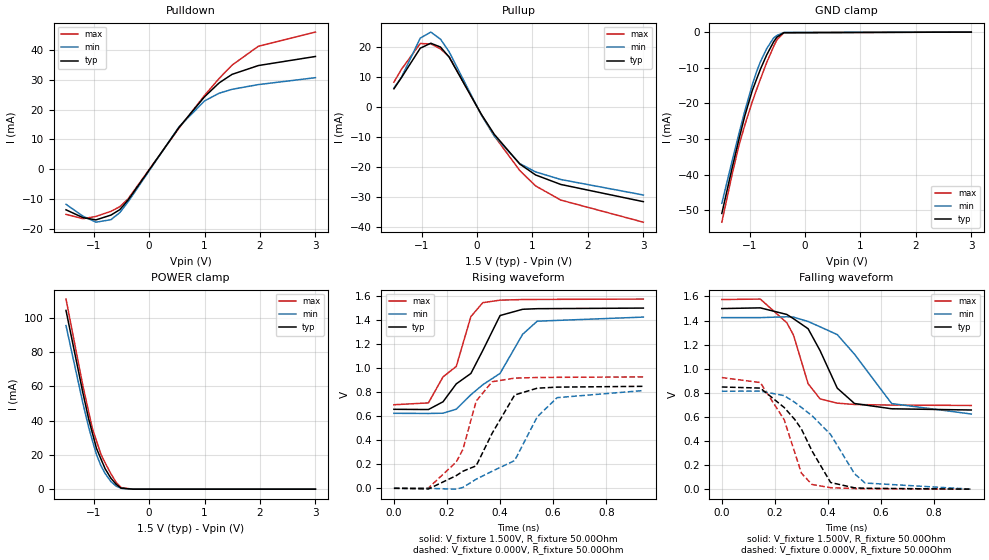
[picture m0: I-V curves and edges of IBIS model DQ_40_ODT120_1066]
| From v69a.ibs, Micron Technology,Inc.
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| MODEL DQ_40_ODT120_1066 (40 Ohm Data I/O with 120ohm ODT, 800/1066Mbps)
[Model]   DQ_40_ODT120_1066
Model_type   I/O
Vinl = 575.000mV
Vinh = 925.000mV
Vmeas = 750.000mV
Vref = 750.000mV
Cref = 0.0pF
Rref = 25.000Ohm
|   typ   min   max
C_comp   1.25pF   1.11pF   1.41pF
| Note: C_comp changes when the ODT circuit is enabled.
[Model Spec]
| Input threshold voltage corners
Vinl   0.5750V   0.5375V   0.6125V
Vinh   0.9250V   0.8875V   0.9625V
| Measurement voltage corners
Vmeas   0.7500V   0.7125V   0.7875V
| Timing spec test load voltage corners
Vref   0.7500V   0.7125V   0.7875V
[Receiver Thresholds]
Vth   =  0.750V
Vth_min  =  0.735V
Vth_max  =  0.765V
Vinh_ac  =  0.175V
Vinh_dc  =  0.100V
Vinl_ac  = -0.175V
Vinl_dc  = -0.100V
Tslew_ac =  5.000ns |Not specified, so set to high value
Threshold_sensitivity = 0.50
Reference_supply Pullup_ref
[Voltage Range]   1.5000V   1.4250V   1.5750V
[Pullup Reference]   1.5000V   1.4250V   1.5750V
| Junction Temperature (Ambient temp is 35C typ, 95C min, 0C max)
[Temperature Range]   50.0   110.0   0.0
[Add Submodel]
| Submodel Name   Mode
120ohm_ODT_1066   Non-Driving
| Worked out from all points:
|   slope of the pulldown table from 0 to 0.225 V, typ, clamps not added: 37.3 ohm
|   slope of the pullup table from 0 to 0.225 V, typ, clamps not added: 33.3 ohm
|   GND clamp passes 1 mA (typ) near -0.48 V on its own axis
|   POWER clamp passes 1 mA (typ) near -0.54 V on its own axis
|   falling waveform, V_fixture 1.500V, R_fixture 50.00Ohm: 20-80 % time 114ps typ, 151ps min, 90.5ps max; typ from 1.5 V to 0.657 V
|   rising waveform, V_fixture 1.500V, R_fixture 50.00Ohm: 20-80 % time 147ps typ, 188ps min, 116ps max; typ from 0.657 V to 1.5 V
|   rising waveform, V_fixture 0.000V, R_fixture 50.00Ohm: 20-80 % time 123ps typ, 153ps min, 104ps max; typ from 0 V to 0.848 V
|   falling waveform, V_fixture 0.000V, R_fixture 50.00Ohm: 20-80 % time 133ps typ, 173ps min, 107ps max; typ from 0.848 V to 0 V
[Pulldown]
|   Voltage   I(typ)   I(min)   I(max)
-1.5V     -13.6mA    -11.75mA   -15.12mA
-1.195V   -16.21mA   -15.72mA   -16.58mA
-960mV    -16.98mA   -17.75mA   -15.83mA
-690mV    -15.38mA   -16.91mA   -14.11mA
-530mV    -13.56mA   -14.54mA   -12.57mA
-380mV    -10.33mA   -10.94mA   -9.938mA
540mV     14.03mA    14.24mA    13.81mA
1V        24.29mA    22.9mA     24.74mA
1.265V    28.96mA    25.48mA    30.46mA
1.495V    31.78mA    26.77mA    34.87mA
1.97V     34.74mA    28.36mA    41.2mA
3V        37.78mA    30.67mA    45.95mA
[GND Clamp]
|   Voltage   I(typ)   I(min)   I(max)
-1.5V     -50.86mA   -48.03mA   -53.31mA
-1.32V    -38.49mA   -36.47mA   -40.31mA
-1.195V   -30.28mA   -28.67mA   -32mA
-1.085V   -23.47mA   -22.1mA    -26.06mA
-950mV    -16.36mA   -14.72mA   -19.5mA
-875mV    -13.3mA    -11.18mA   -16.21mA
-805mV    -10.44mA   -8.35mA    -13.23mA
-690mV    -6.381mA   -4.61mA    -8.515mA
-565mV    -2.71mA    -1.629mA   -4.002mA
-505mV    -1.389mA   -935.1uA   -2.13mA
-380mV    -171.4uA   -110.2uA   -180.2uA
3V        0A         0A         0A
[Pullup]
|   Voltage   I(typ)   I(min)   I(max)
-1.5V     6.153mA    6.385mA    8.388mA
-1.365V   9.878mA    9.978mA    12.67mA
-1.025V   19.77mA    23.13mA    21.32mA
-835mV    21.43mA    25.16mA    21.21mA
-660mV    20.15mA    22.79mA    19.54mA
-505mV    16.8mA     18.6mA     16.93mA
80mV      -2.482mA   -2.723mA   -2.581mA
310mV     -9.086mA   -9.637mA   -9.633mA
770mV     -19.05mA   -18.9mA    -21.22mA
1.055V    -22.71mA   -21.69mA   -26.38mA
1.51V     -25.9mA    -24.24mA   -31.14mA
3V        -31.67mA   -29.44mA   -38.55mA
[POWER Clamp]
|   Voltage   I(typ)   I(min)   I(max)
-1.5V     104.2mA    95.33mA    110.8mA
-1.195V   56.08mA    50.05mA    60.2mA
-1.09V    40.77mA    35.95mA    44.95mA
-1.025V   32.84mA    28.43mA    35.51mA
-950mV    23.76mA    20.16mA    28.1mA
-870mV    17.62mA    13.67mA    20.38mA
-795mV    11.95mA    9.2mA      15.38mA
-690mV    6.402mA    4.437mA    8.988mA
-595mV    2.805mA    1.754mA    3.913mA
-505mV    588.2uA    491.1uA    931.8uA
-300mV    1.53uA     2.94uA     1.674uA
3V        0A         0A         0A
[Ramp]
R_load = 50.00Ohm
|   typ   min   max
dV/dt_r   508.798mV/123.002ps 487.677mV/153.142ps 555.841mV/104.138ps
dV/dt_f   504.967mV/113.836ps 479.854mV/151.141ps 527.439mV/90.495ps
[Falling Waveform]
V_fixture = 1.500V
V_fixture_min = 1.425V
V_fixture_max = 1.575V
R_fixture = 50.00Ohm
|   Time   V(typ)   V(min)   V(max)
0s        1.499V     1.424V     1.574V
145ps     1.505V     1.424V     1.578V
245ps     1.45V      1.431V     1.381V
270ps     1.415V     1.428V     1.279V
325ps     1.332V     1.392V     875.9mV
370ps     1.151V     1.348V     749.8mV
435ps     838.6mV    1.283V     714.1mV
500ps     711.1mV    1.12V      703mV
640ps     667.3mV    710.7mV    697.8mV
940ps     657.2mV    623.8mV    695.1mV
[Rising Waveform]
V_fixture = 1.500V
V_fixture_min = 1.425V
V_fixture_max = 1.575V
R_fixture = 50.00Ohm
|   Time   V(typ)   V(min)   V(max)
0s        657.2mV    623.8mV    695.1mV
130ps     655.3mV    622.6mV    710.5mV
185ps     719.7mV    624.8mV    926.5mV
235ps     868.8mV    658.2mV    1.014V
290ps     955.1mV    778.4mV    1.428V
335ps     1.147V     861.3mV    1.544V
400ps     1.437V     956.1mV    1.565V
485ps     1.489V     1.281V     1.57V
540ps     1.494V     1.39V      1.571V
940ps     1.499V     1.424V     1.574V
[Rising Waveform]
V_fixture = 0.000V
V_fixture_min = 0.000V
V_fixture_max = 0.000V
R_fixture = 50.00Ohm
|   Time   V(typ)   V(min)   V(max)
0s        250uV      307.8uV    134.6uV
130ps     -5.431mV   -289.2uV   2.591mV
235ps     105.8mV    -7.022mV   219.4mV
260ps     142.1mV    7.733mV    323.5mV
310ps     187.3mV    75.89mV    725.3mV
370ps     457.2mV    142.1mV    886.4mV
455ps     776.4mV    230.8mV    916.6mV
540ps     832.8mV    594.1mV    921.6mV
615ps     841.6mV    754.1mV    923.1mV
940ps     848.2mV    813.1mV    926.5mV
[Falling Waveform]
V_fixture = 0.000V
V_fixture_min = 0.000V
V_fixture_max = 0.000V
R_fixture = 50.00Ohm
|   Time   V(typ)   V(min)   V(max)
0s        848.2mV    813.1mV    926.5mV
145ps     839.2mV    814.2mV    885mV
235ps     677.9mV    776.4mV    576.3mV
275ps     578.1mV    720.9mV    302.7mV
300ps     498.6mV    678.4mV    132.5mV
340ps     316.7mV    609.5mV    38.8mV
410ps     55.34mV    453.9mV    12.38mV
500ps     11.17mV    128.3mV    5.346mV
540ps     7.65mV     51.18mV    4.149mV
940ps     250uV      307.8uV    134.6uV
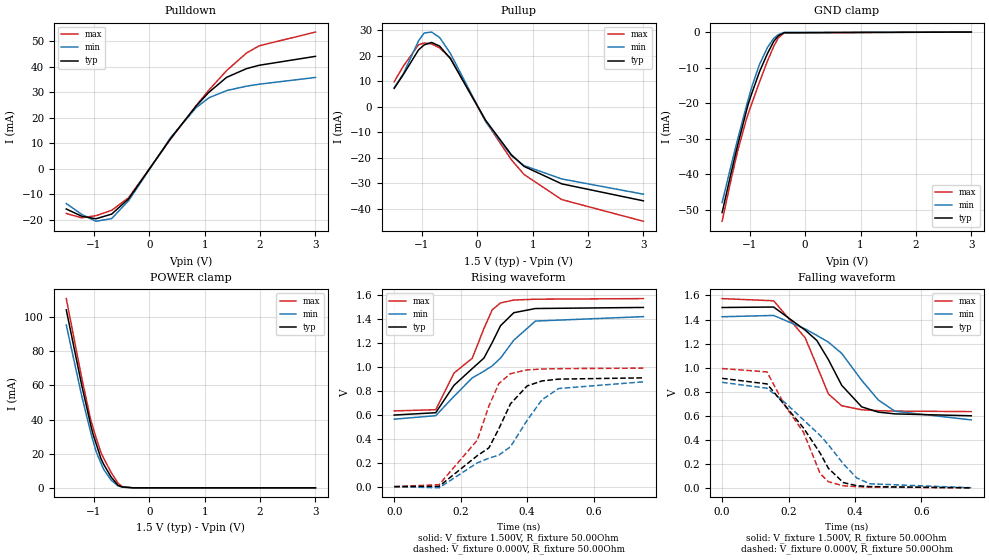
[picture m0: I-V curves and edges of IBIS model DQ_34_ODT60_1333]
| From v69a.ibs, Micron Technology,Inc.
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| MODEL DQ_34_ODT60_1333 (34 Ohm Data I/O with 60ohm ODT, 1333Mbps)
[Model]   DQ_34_ODT60_1333
Model_type   I/O
Vinl = 600.000mV
Vinh = 900.000mV
Vmeas = 750.000mV
Vref = 750.000mV
Cref = 0.0pF
Rref = 25.000Ohm
|   typ   min   max
C_comp   1.25pF   1.09pF   1.43pF
| Note: C_comp changes when the ODT circuit is enabled.
[Model Spec]
| Input threshold voltage corners
Vinl   0.6000V   0.5625V   0.6375V
Vinh   0.9000V   0.8625V   0.9375V
| Measurement voltage corners
Vmeas   0.7500V   0.7125V   0.7875V
| Timing spec test load voltage corners
Vref   0.7500V   0.7125V   0.7875V
[Receiver Thresholds]
Vth   =  0.750V
Vth_min  =  0.735V
Vth_max  =  0.765V
Vinh_ac  =  0.150V
Vinh_dc  =  0.100V
Vinl_ac  = -0.150V
Vinl_dc  = -0.100V
Tslew_ac =  5.000ns |Not specified, so set to high value
Threshold_sensitivity = 0.50
Reference_supply Pullup_ref
[Voltage Range]   1.5000V   1.4250V   1.5750V
[Pullup Reference]   1.5000V   1.4250V   1.5750V
| Junction Temperature (Ambient temp is 35C typ, 95C min, 0C max)
[Temperature Range]   50.0   110.0   0.0
[Add Submodel]
| Submodel Name   Mode
60ohm_ODT_1333   Non-Driving
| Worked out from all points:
|   slope of the pulldown table from 0 to 0.225 V, typ, clamps not added: 31.9 ohm
|   slope of the pullup table from 0 to 0.225 V, typ, clamps not added: 28.4 ohm
|   GND clamp passes 1 mA (typ) near -0.48 V on its own axis
|   POWER clamp passes 1 mA (typ) near -0.53 V on its own axis
|   falling waveform, V_fixture 1.500V, R_fixture 50.00Ohm: 20-80 % time 131ps typ, 172ps min, 110ps max; typ from 1.5 V to 0.599 V
|   rising waveform, V_fixture 1.500V, R_fixture 50.00Ohm: 20-80 % time 150ps typ, 192ps min, 121ps max; typ from 0.599 V to 1.5 V
|   rising waveform, V_fixture 0.000V, R_fixture 50.00Ohm: 20-80 % time 155ps typ, 201ps min, 123ps max; typ from 0 V to 0.911 V
|   falling waveform, V_fixture 0.000V, R_fixture 50.00Ohm: 20-80 % time 138ps typ, 179ps min, 112ps max; typ from 0.911 V to 0 V
[Pulldown]
|   Voltage   I(typ)   I(min)   I(max)
-1.5V     -15.86mA   -13.71mA   -17.64mA
-1.22V    -18.7mA    -17.99mA   -19.3mA
-965mV    -19.7mA    -20.68mA   -18.5mA
-680mV    -17.86mA   -19.62mA   -16.37mA
-375mV    -11.88mA   -12.6mA    -11.45mA
390mV     11.99mA    12.36mA    11.75mA
845mV     24.56mA    23.92mA    24.71mA
1.075V    29.95mA    27.78mA    30.82mA
1.395V    35.82mA    30.62mA    38.47mA
1.755V    39.25mA    32.36mA    45.39mA
1.985V    40.57mA    33.14mA    48.21mA
3V        44.07mA    35.78mA    53.61mA
[GND Clamp]
|   Voltage   I(typ)   I(min)   I(max)
-1.5V     -50.86mA   -48.03mA   -53.31mA
-1.335V   -39.51mA   -37.41mA   -41.36mA
-1.22V    -31.91mA   -30.23mA   -33.59mA
-1.06V    -22.14mA   -20.74mA   -24.46mA
-1.03V    -20.37mA   -19.08mA   -23.1mA
-960mV    -17.09mA   -15.22mA   -19.96mA
-825mV    -11.18mA   -9.113mA   -14.07mA
-680mV    -6.012mA   -4.321mA   -8.138mA
-565mV    -2.562mA   -1.714mA   -3.942mA
-485mV    -1.053mA   -743.8uA   -1.64mA
-380mV    -208.9uA   -97.58uA   -211uA
3V        0A         0A         0A
[Pullup]
|   Voltage   I(typ)   I(min)   I(max)
-1.5V     7.178mA    7.449mA    9.786mA
-1.34V    12.44mA    12.71mA    15.73mA
-1.06V    22.29mA    25.85mA    24.28mA
-960mV    24.22mA    28.89mA    24.98mA
-825mV    25.21mA    29.28mA    24.64mA
-680mV    23.76mA    27.16mA    23.08mA
-485mV    18.85mA    20.88mA    19.1mA
155mV     -5.461mA   -5.981mA   -5.833mA
615mV     -18.83mA   -19.23mA   -20.79mA
845mV     -23.43mA   -23.12mA   -26.61mA
1.525V    -30.28mA   -28.36mA   -36.46mA
3V        -36.95mA   -34.34mA   -44.97mA
[POWER Clamp]
|   Voltage   I(typ)   I(min)   I(max)
-1.5V     104.2mA    95.33mA    110.8mA
-1.22V    59.88mA    53.65mA    64.17mA
-1.06V    36.99mA    32.51mA    40.06mA
-1.025V   32.28mA    28.5mA     36.2mA
-960mV    25.75mA    21.1mA     29.08mA
-875mV    17.23mA    14.62mA    20.76mA
-825mV    13.81mA    10.81mA    17.3mA
-690mV    6.286mA    4.503mA    9.027mA
-565mV    1.438mA    1.112mA    2.719mA
-490mV    520.5uA    387uA      712uA
-290mV    1.769uA    1.056uA    286.1nA
3V        0A         0A         0A
[Ramp]
R_load = 50.00Ohm
|   typ   min   max
dV/dt_r   546.393mV/154.671ps 526.113mV/201.400ps 595.210mV/122.526ps
dV/dt_f   540.353mV/131.172ps 514.673mV/171.813ps 564.059mV/110.021ps
[Falling Waveform]
V_fixture = 1.500V
V_fixture_min = 1.425V
V_fixture_max = 1.575V
R_fixture = 50.00Ohm
|   Time   V(typ)   V(min)   V(max)
0s        1.5V       1.423V     1.574V
155ps     1.504V     1.434V     1.556V
250ps     1.312V     1.322V     1.248V
285ps     1.226V     1.268V     1.016V
320ps     1.066V     1.212V     780.6mV
360ps     852.7mV    1.118V     682.7mV
420ps     673.8mV    894.7mV    649.5mV
470ps     630mV      731.1mV    641.8mV
520ps     615.1mV    637mV      638.4mV
750ps     599.3mV    564.9mV    634mV
[Rising Waveform]
V_fixture = 1.500V
V_fixture_min = 1.425V
V_fixture_max = 1.575V
R_fixture = 50.00Ohm
|   Time   V(typ)   V(min)   V(max)
0s        599.3mV    564.9mV    634mV
125ps     619mV      594mV      644mV
180ps     848.3mV    756.1mV    951mV
235ps     988.4mV    910.5mV    1.075V
270ps     1.076V     966.4mV    1.323V
295ps     1.206V     1.011V     1.48V
320ps     1.347V     1.076V     1.538V
360ps     1.456V     1.226V     1.562V
425ps     1.491V     1.386V     1.569V
750ps     1.5V       1.423V     1.574V
[Rising Waveform]
V_fixture = 0.000V
V_fixture_min = 0.000V
V_fixture_max = 0.000V
R_fixture = 50.00Ohm
|   Time   V(typ)   V(min)   V(max)
0s        -4.765uV   687.2uV    159.9uV
135ps     2.627mV    -9.896mV   16.69mV
250ps     258.9mV    199mV      388.6mV
285ps     324.5mV    238mV      674.7mV
315ps     484.8mV    264.1mV    863mV
350ps     693.4mV    334.1mV    945.8mV
400ps     842.9mV    555.3mV    977.4mV
445ps     885mV      727.9mV    984.7mV
495ps     900.1mV    821.4mV    987.7mV
750ps     910.7mV    877.5mV    992.2mV
[Falling Waveform]
V_fixture = 0.000V
V_fixture_min = 0.000V
V_fixture_max = 0.000V
R_fixture = 50.00Ohm
|   Time   V(typ)   V(min)   V(max)
0s        910.7mV    877.5mV    992.2mV
135ps     864.5mV    828.8mV    964.4mV
190ps     683.1mV    707.1mV    679.7mV
245ps     497.8mV    564.8mV    462.6mV
295ps     288.7mV    435.7mV    118.3mV
320ps     162mV      358mV      50.32mV
365ps     43.43mV    198.5mV    17.39mV
405ps     17.97mV    82.8mV     9.568mV
445ps     10.09mV    33.45mV    6.161mV
750ps     -4.765uV   687.2uV    159.9uV
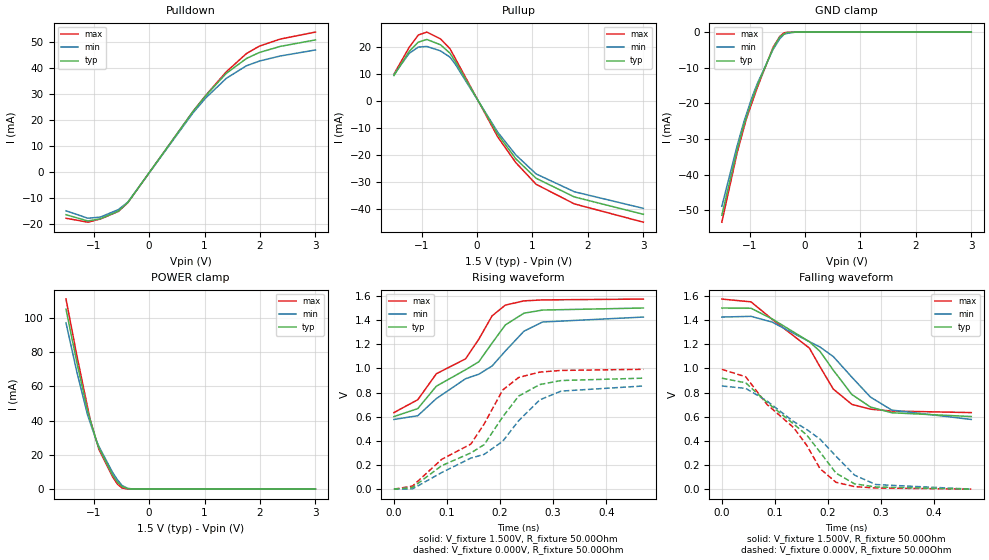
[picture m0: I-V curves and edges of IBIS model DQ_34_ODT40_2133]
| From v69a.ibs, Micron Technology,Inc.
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| MODEL DQ_34_ODT40_2133 (34 Ohm Data I/O with 40ohm ODT, 1866/2133 Mbps)
[Model]   DQ_34_ODT40_2133
Model_type   I/O
Vinl = 625.000mV
Vinh = 875.000mV
Vmeas = 750.000mV
Vref = 750.000mV
Cref = 0.0pF
Rref = 25.000Ohm
|   typ   min   max
C_comp   1.19pF   1.04pF   1.35pF
| Note: C_comp changes when the ODT circuit is enabled.
[Model Spec]
| Input threshold voltage corners
Vinl   0.6250V   0.5875V   0.6625V
Vinh   0.8750V   0.8375V   0.9125V
| Measurement voltage corners
Vmeas   0.7500V   0.7125V   0.7875V
| Timing spec test load voltage corners
Vref   0.7500V   0.7125V   0.7875V
[Receiver Thresholds]
Vth   =  0.750V
Vth_min  =  0.735V
Vth_max  =  0.765V
Vinh_ac  =  0.125V
Vinh_dc  =  0.100V
Vinl_ac  = -0.125V
Vinl_dc  = -0.100V
Tslew_ac =  5.000ns |Not specified, so set to high value
Threshold_sensitivity = 0.50
Reference_supply Pullup_ref
[Voltage Range]   1.5000V   1.4250V   1.5750V
[Pullup Reference]   1.5000V   1.4250V   1.5750V
| Junction Temperature (Ambient temp is 35C typ, 95C min, 0C max)
[Temperature Range]   50.0   110.0   0.0
[Add Submodel]
| Submodel Name   Mode
40ohm_ODT_2133   Non-Driving
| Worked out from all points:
|   slope of the pulldown table from 0 to 0.225 V, typ, clamps not added: 32.5 ohm
|   slope of the pullup table from 0 to 0.225 V, typ, clamps not added: 28.9 ohm
|   GND clamp passes 1 mA (typ) near -0.42 V on its own axis
|   POWER clamp passes 1 mA (typ) near -0.47 V on its own axis
|   falling waveform, V_fixture 1.500V, R_fixture 50.00Ohm: 20-80 % time 120ps typ, 135ps min, 111ps max; typ from 1.5 V to 0.601 V
|   rising waveform, V_fixture 1.500V, R_fixture 50.00Ohm: 20-80 % time 136ps typ, 153ps min, 121ps max; typ from 0.601 V to 1.5 V
|   rising waveform, V_fixture 0.000V, R_fixture 50.00Ohm: 20-80 % time 141ps typ, 157ps min, 124ps max; typ from 0 V to 0.919 V
|   falling waveform, V_fixture 0.000V, R_fixture 50.00Ohm: 20-80 % time 123ps typ, 138ps min, 112ps max; typ from 0.919 V to 0 V
[Pulldown]
|   Voltage   I(typ)   I(min)   I(max)
-1.5V     -16.29mA   -14.8mA    -17.64mA
-1.105V   -18.68mA   -17.63mA   -19.15mA
-880mV    -17.85mA   -17.19mA   -17.94mA
-555mV    -14.94mA   -14.32mA   -15.02mA
-385mV    -11.64mA   -11.48mA   -11.69mA
795mV     23.36mA    22.81mA    23.33mA
1.02V     29.25mA    28.38mA    29.37mA
1.39V     37.78mA    35.88mA    38.36mA
1.755V    43.51mA    40.72mA    45.39mA
1.99V     45.82mA    42.53mA    48.26mA
2.365V    48.13mA    44.46mA    50.94mA
3V        50.62mA    46.76mA    53.61mA
[GND Clamp]
|   Voltage   I(typ)   I(min)   I(max)
-1.5V     -51.33mA   -48.85mA   -53.31mA
-1.225V   -33.17mA   -31.96mA   -33.91mA
-1.11V    -26.38mA   -25.59mA   -27.31mA
-1.06V    -24mA      -23.21mA   -24.46mA
-955mV    -19.04mA   -18.24mA   -19.74mA
-855mV    -14.8mA    -14.26mA   -15.35mA
-575mV    -4.569mA   -4.842mA   -4.255mA
-455mV    -1.373mA   -1.876mA   -1.232mA
-380mV    -600.5uA   -637.3uA   -211uA
-330mV    -105.7uA   -382.3uA   -79.03uA
-165mV    -2.061uA   -3.044uA   0A
3V        0A         0A         0A
[Pullup]
|   Voltage   I(typ)   I(min)   I(max)
-1.5V     9.275mA    9.623mA    9.786mA
-1.225V   18.22mA    17.48mA    19.7mA
-1.06V    21.64mA    19.81mA    24.28mA
-905mV    22.64mA    20.04mA    25.36mA
-660mV    20.66mA    18.41mA    22.85mA
-490mV    17.59mA    16.11mA    19.25mA
-390mV    14.39mA    13.4mA     15.49mA
375mV     -12.49mA   -11.73mA   -13.49mA
700mV     -21.55mA   -20.1mA    -22.95mA
1.065V    -28.73mA   -27.11mA   -30.95mA
1.755V    -35.63mA   -33.71mA   -38.2mA
3V        -42.05mA   -39.85mA   -44.97mA
[POWER Clamp]
|   Voltage   I(typ)   I(min)   I(max)
-1.5V     104.9mA    96.95mA    110.8mA
-1.305V   73.96mA    68.35mA    78.05mA
-1.11V    45.47mA    43.15mA    47.59mA
-1.06V    40.01mA    38.39mA    40.06mA
-955mV    28.63mA    28.51mA    28.54mA
-905mV    24.01mA    24.84mA    23.06mA
-660mV    8.35mA     9.771mA    7.255mA
-570mV    3.953mA    5.39mA     2.853mA
-490mV    1.557mA    2.191mA    712uA
-385mV    314.2uA    439.4uA    73.92uA
-265mV    10.67uA    38.19uA    0A
3V        0A         0A         0A
[Ramp]
R_load = 50.00Ohm
|   typ   min   max
dV/dt_r   551.471mV/140.807ps 512.490mV/156.929ps 595.210mV/123.769ps
dV/dt_f   539.233mV/119.683ps 508.442mV/135.202ps 564.059mV/110.832ps
[Falling Waveform]
V_fixture = 1.500V
V_fixture_min = 1.425V
V_fixture_max = 1.575V
R_fixture = 50.00Ohm
|   Time   V(typ)   V(min)   V(max)
0s        1.5V       1.425V     1.574V
55ps      1.498V     1.431V     1.551V
95ps      1.409V     1.383V     1.406V
165ps     1.221V     1.221V     1.168V
185ps     1.141V     1.177V     1.013V
210ps     985.3mV    1.098V     828.9mV
245ps     783.8mV    927.2mV    702.2mV
280ps     680mV      762.7mV    662.4mV
320ps     632.7mV    655.1mV    646.8mV
470ps     601.2mV    577.1mV    634mV
[Rising Waveform]
V_fixture = 1.500V
V_fixture_min = 1.425V
V_fixture_max = 1.575V
R_fixture = 50.00Ohm
|   Time   V(typ)   V(min)   V(max)
0s        601.2mV    577.1mV    634mV
45ps      667.2mV    608.1mV    740.8mV
80ps      853mV      750.3mV    955.6mV
135ps     988.6mV    914.4mV    1.079V
160ps     1.055V     951.7mV    1.242V
185ps     1.21V      1.02V      1.435V
210ps     1.36V      1.144V     1.524V
245ps     1.457V     1.308V     1.559V
280ps     1.483V     1.384V     1.567V
470ps     1.5V       1.425V     1.574V
[Rising Waveform]
V_fixture = 0.000V
V_fixture_min = 0.000V
V_fixture_max = 0.000V
R_fixture = 50.00Ohm
|   Time   V(typ)   V(min)   V(max)
0s        -16.13uV   137.9uV    159.9uV
35ps      13.83mV    2.175mV    25.31mV
90ps      194.5mV    137.6mV    247mV
145ps     300mV      257.3mV    373.5mV
170ps     368.6mV    288mV      539.7mV
205ps     598.5mV    396.6mV    820.8mV
235ps     770.8mV    566.8mV    924.6mV
275ps     866.4mV    739.9mV    969.5mV
315ps     899.5mV    811.9mV    983.2mV
470ps     919.1mV    854.3mV    992.2mV
[Falling Waveform]
V_fixture = 0.000V
V_fixture_min = 0.000V
V_fixture_max = 0.000V
R_fixture = 50.00Ohm
|   Time   V(typ)   V(min)   V(max)
0s        919.1mV    854.3mV    992.2mV
45ps      880.3mV    834.5mV    930.3mV
85ps      719.5mV    730.1mV    701.6mV
135ps     540.6mV    560.7mV    511mV
160ps     448.2mV    493.8mV    363mV
185ps     307.2mV    414.3mV    170mV
215ps     133.2mV    273.5mV    57.05mV
250ps     43.92mV    116.3mV    21.15mV
290ps     18.26mV    38.31mV    9.758mV
470ps     -16.13uV   137.9uV    159.9uV
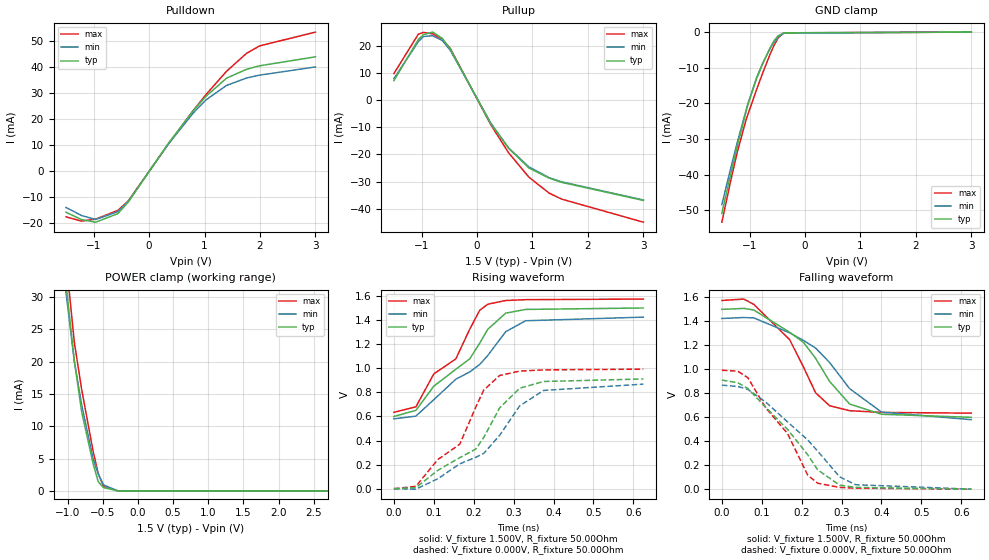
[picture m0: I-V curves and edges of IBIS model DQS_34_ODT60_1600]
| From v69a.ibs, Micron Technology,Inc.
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| MODEL DQS_34_ODT60_1600 (34 Ohm Data Strobe I/O with 60ohm ODT, 1600Mbps)
[Model]   DQS_34_ODT60_1600
Model_type   I/O
Vinl = 600.000mV
Vinh = 900.000mV
Vmeas = 750.000mV
Vref = 750.000mV
Cref = 0.0pF
Rref = 25.000Ohm
|   typ   min   max
C_comp   1.23pF   1.09pF   1.39pF
| Note: C_comp changes when the ODT circuit is enabled.
[Model Spec]
| Input threshold voltage corners
Vinl   0.6000V   0.5625V   0.6375V
Vinh   0.9000V   0.8625V   0.9375V
| Measurement voltage corners
Vmeas   0.7500V   0.7125V   0.7875V
| Timing spec test load voltage corners
Vref   0.7500V   0.7125V   0.7875V
|[Receiver Thresholds]
|Vth   =  0.750V
|Vth_min  =  0.735V
|Vth_max  =  0.765V
|Vinh_ac  =  0.150V
|Vinh_dc  =  0.100V
|Vinl_ac  = -0.150V
|Vinl_dc  = -0.100V
|Tslew_ac =  5.000ns |Not specified, so set to high value
|Threshold_sensitivity = 0.50
|Reference_supply Pullup_ref
[Receiver Thresholds]
Vcross_low   = 0.600V
Vcross_high  = 0.900V
Vdiff_ac   = 300mV
Vdiff_dc   = 200mV
Tdiffslew_ac = 10.000ns |Not specified, so set to high value
[Voltage Range]   1.5000V   1.4250V   1.5750V
[Pullup Reference]   1.5000V   1.4250V   1.5750V
| Junction Temperature (Ambient temp is 35C typ, 95C min, 0C max)
[Temperature Range]   50.0   110.0   0.0
[Add Submodel]
| Submodel Name   Mode
60ohm_ODT_1600   Non-Driving
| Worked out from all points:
|   slope of the pulldown table from 0 to 0.225 V, typ, clamps not added: 31.9 ohm
|   slope of the pullup table from 0 to 0.225 V, typ, clamps not added: 28.4 ohm
|   GND clamp passes 1 mA (typ) near -0.48 V on its own axis
|   POWER clamp passes 1 mA (typ) near -0.53 V on its own axis
|   falling waveform, V_fixture 1.500V, R_fixture 50.00Ohm: 20-80 % time 132ps typ, 150ps min, 110ps max; typ from 1.5 V to 0.599 V
|   rising waveform, V_fixture 1.500V, R_fixture 50.00Ohm: 20-80 % time 150ps typ, 165ps min, 121ps max; typ from 0.599 V to 1.5 V
|   rising waveform, V_fixture 0.000V, R_fixture 50.00Ohm: 20-80 % time 156ps typ, 170ps min, 123ps max; typ from 0 V to 0.911 V
|   falling waveform, V_fixture 0.000V, R_fixture 50.00Ohm: 20-80 % time 138ps typ, 154ps min, 112ps max; typ from 0.911 V to 0 V
[Pulldown]
|   Voltage   I(typ)   I(min)   I(max)
-1.5V     -15.86mA   -14.03mA   -17.64mA
-1.22V    -18.7mA    -17.12mA   -19.3mA
-965mV    -19.7mA    -18.66mA   -18.5mA
-565mV    -16.41mA   -15.64mA   -15.16mA
-375mV    -11.88mA   -11.57mA   -11.45mA
340mV     10.5mA     10.24mA    10.27mA
795mV     23.28mA    22.39mA    23.33mA
1.025V    28.85mA    27.46mA    29.51mA
1.395V    35.82mA    33.03mA    38.47mA
1.755V    39.25mA    35.89mA    45.39mA
1.99V     40.6mA     37mA       48.26mA
3V        44.07mA    40.17mA    53.61mA
[GND Clamp]
|   Voltage   I(typ)   I(min)   I(max)
-1.5V     -50.86mA   -48.39mA   -53.31mA
-1.335V   -39.51mA   -37.89mA   -41.36mA
-1.22V    -31.91mA   -30.85mA   -33.59mA
-1.06V    -22.14mA   -21.75mA   -24.46mA
-1.03V    -20.37mA   -20.11mA   -23.1mA
-875mV    -13.13mA   -12.88mA   -16.2mA
-765mV    -8.986mA   -8.82mA    -11.56mA
-635mV    -4.662mA   -4.732mA   -6.435mA
-565mV    -2.562mA   -2.983mA   -3.942mA
-485mV    -1.053mA   -1.384mA   -1.64mA
-380mV    -208.9uA   -292.7uA   -211uA
3V        0A         0A         0A
[Pullup]
|   Voltage   I(typ)   I(min)   I(max)
-1.5V     7.178mA    7.94mA     9.786mA
-1.06V    22.29mA    21.51mA    24.28mA
-965mV    24.15mA    23.45mA    24.95mA
-800mV    25.06mA    23.7mA     24.38mA
-630mV    22.8mA     22.01mA    22.38mA
-485mV    18.85mA    18.42mA    19.1mA
245mV     -8.61mA    -8.358mA   -8.964mA
565mV     -17.63mA   -17.57mA   -19.3mA
935mV     -25mA      -24.59mA   -28.39mA
1.3V      -28.74mA   -28.56mA   -34.25mA
1.525V    -30.28mA   -30.1mA    -36.46mA
3V        -36.95mA   -36.79mA   -44.97mA
[POWER Clamp]
|   Voltage   I(typ)   I(min)   I(max)
-1.5V     104.2mA    96.04mA    110.8mA
-1.22V    59.88mA    55.04mA    64.17mA
-1.155V   50.11mA    46.13mA    54.38mA
-1.06V    36.99mA    35.03mA    40.06mA
-1.025V   32.28mA    30.95mA    36.2mA
-905mV    20.23mA    20.1mA     23.06mA
-800mV    12.24mA    13.34mA    15.7mA
-635mV    4.119mA    4.874mA    6.02mA
-565mV    1.438mA    2.643mA    2.719mA
-490mV    520.5uA    937.2uA    712uA
-285mV    1.423uA    9.711uA    221nA
3V        0A         0A         0A
[Ramp]
R_load = 50.00Ohm
|   typ   min   max
dV/dt_r   546.393mV/156.397ps 520.588mV/170.034ps 595.210mV/122.997ps
dV/dt_f   540.353mV/132.270ps 506.534mV/149.759ps 564.059mV/110.162ps
[Falling Waveform]
V_fixture = 1.500V
V_fixture_min = 1.425V
V_fixture_max = 1.575V
R_fixture = 50.00Ohm
|   Time   V(typ)   V(min)   V(max)
0s        1.5V       1.424V     1.574V
55ps      1.508V     1.432V     1.586V
80ps      1.495V     1.429V     1.542V
170ps     1.309V     1.304V     1.247V
205ps     1.223V     1.24V      1.016V
235ps     1.091V     1.177V     803.7mV
270ps     899.5mV    1.057V     695.9mV
320ps     710.4mV    839.2mV    654.8mV
400ps     624.9mV    643.4mV    640.4mV
625ps     599.3mV    579.8mV    634mV
[Rising Waveform]
V_fixture = 1.500V
V_fixture_min = 1.425V
V_fixture_max = 1.575V
R_fixture = 50.00Ohm
|   Time   V(typ)   V(min)   V(max)
0s        599.3mV    579.8mV    634mV
55ps      650.3mV    602.5mV    679.2mV
100ps     851.2mV    739mV      953.1mV
155ps     990.8mV    908.5mV    1.077V
190ps     1.078V     969.7mV    1.324V
215ps     1.208V     1.031V     1.481V
235ps     1.322V     1.105V     1.531V
280ps     1.457V     1.303V     1.562V
330ps     1.488V     1.394V     1.569V
625ps     1.5V       1.424V     1.574V
[Rising Waveform]
V_fixture = 0.000V
V_fixture_min = 0.000V
V_fixture_max = 0.000V
R_fixture = 50.00Ohm
|   Time   V(typ)   V(min)   V(max)
0s        -4.765uV   270.2uV    159.9uV
55ps      8.779mV    -3.827mV   19.75mV
110ps     152.5mV    82.57mV    242.2mV
165ps     257.8mV    206.4mV    369.3mV
205ps     328.7mV    260.5mV    676.1mV
225ps     424.7mV    292.7mV    818.2mV
265ps     671mV      443.1mV    939.8mV
315ps     833.9mV    687.1mV    976.2mV
375ps     889.9mV    815.6mV    986.2mV
625ps     910.7mV    867.9mV    992.2mV
[Falling Waveform]
V_fixture = 0.000V
V_fixture_min = 0.000V
V_fixture_max = 0.000V
R_fixture = 50.00Ohm
|   Time   V(typ)   V(min)   V(max)
0s        910.7mV    867.9mV    992.2mV
40ps      887.4mV    856.4mV    984.3mV
65ps      840.6mV    832.4mV    930.6mV
110ps     682.4mV    726.7mV    678.7mV
165ps     497.1mV    559.9mV    461.8mV
215ps     288.1mV    411.7mV    117.8mV
240ps     161.5mV    318mV      49.88mV
295ps     33.6mV     103.4mV    14.44mV
335ps     14.87mV    37.3mV     8.162mV
625ps     -4.765uV   270.2uV    159.9uV
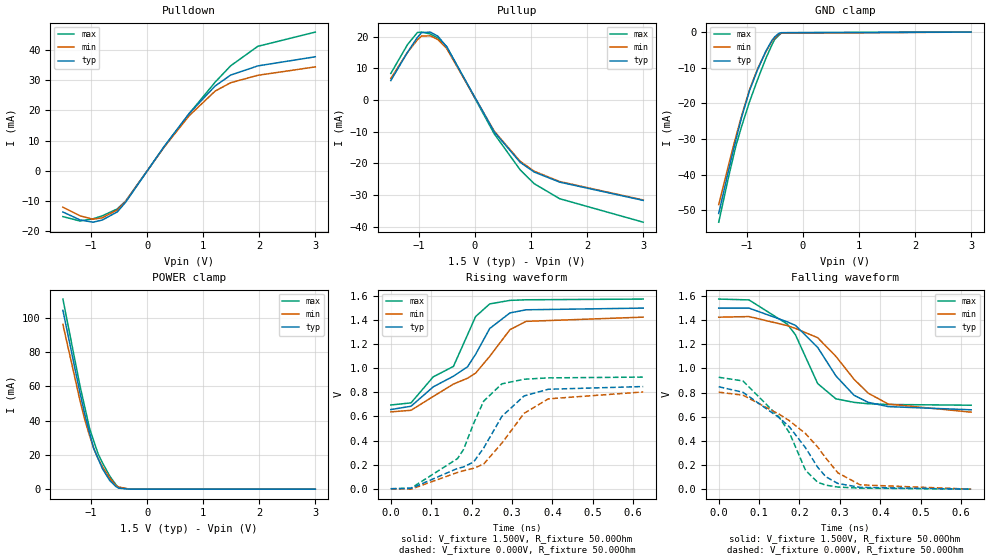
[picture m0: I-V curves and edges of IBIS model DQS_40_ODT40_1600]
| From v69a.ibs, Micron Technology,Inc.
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| MODEL DQS_40_ODT40_1600 (40 Ohm Data Strobe I/O with 40ohm ODT, 1600Mbps)
[Model]   DQS_40_ODT40_1600
Model_type   I/O
Vinl = 600.000mV
Vinh = 900.000mV
Vmeas = 750.000mV
Vref = 750.000mV
Cref = 0.0pF
Rref = 25.000Ohm
|   typ   min   max
C_comp   1.22pF   1.07pF   1.38pF
| Note: C_comp changes when the ODT circuit is enabled.
[Model Spec]
| Input threshold voltage corners
Vinl   0.6000V   0.5625V   0.6375V
Vinh   0.9000V   0.8625V   0.9375V
| Measurement voltage corners
Vmeas   0.7500V   0.7125V   0.7875V
| Timing spec test load voltage corners
Vref   0.7500V   0.7125V   0.7875V
|[Receiver Thresholds]
|Vth   =  0.750V
|Vth_min  =  0.735V
|Vth_max  =  0.765V
|Vinh_ac  =  0.150V
|Vinh_dc  =  0.100V
|Vinl_ac  = -0.150V
|Vinl_dc  = -0.100V
|Tslew_ac =  5.000ns |Not specified, so set to high value
|Threshold_sensitivity = 0.50
|Reference_supply Pullup_ref
[Receiver Thresholds]
Vcross_low   = 0.600V
Vcross_high  = 0.900V
Vdiff_ac   = 300mV
Vdiff_dc   = 200mV
Tdiffslew_ac = 10.000ns |Not specified, so set to high value
[Voltage Range]   1.5000V   1.4250V   1.5750V
[Pullup Reference]   1.5000V   1.4250V   1.5750V
| Junction Temperature (Ambient temp is 35C typ, 95C min, 0C max)
[Temperature Range]   50.0   110.0   0.0
[Add Submodel]
| Submodel Name   Mode
40ohm_ODT_1600   Non-Driving
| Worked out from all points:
|   slope of the pulldown table from 0 to 0.225 V, typ, clamps not added: 37.3 ohm
|   slope of the pullup table from 0 to 0.225 V, typ, clamps not added: 33.3 ohm
|   GND clamp passes 1 mA (typ) near -0.48 V on its own axis
|   POWER clamp passes 1 mA (typ) near -0.54 V on its own axis
|   falling waveform, V_fixture 1.500V, R_fixture 50.00Ohm: 20-80 % time 114ps typ, 133ps min, 90.6ps max; typ from 1.5 V to 0.657 V
|   rising waveform, V_fixture 1.500V, R_fixture 50.00Ohm: 20-80 % time 148ps typ, 163ps min, 117ps max; typ from 0.657 V to 1.5 V
|   rising waveform, V_fixture 0.000V, R_fixture 50.00Ohm: 20-80 % time 127ps typ, 142ps min, 105ps max; typ from 0 V to 0.848 V
|   falling waveform, V_fixture 0.000V, R_fixture 50.00Ohm: 20-80 % time 133ps typ, 149ps min, 107ps max; typ from 0.848 V to 0 V
[Pulldown]
|   Voltage   I(typ)   I(min)   I(max)
-1.5V     -13.6mA    -12.02mA   -15.12mA
-1.195V   -16.21mA   -14.86mA   -16.58mA
-965mV    -16.97mA   -15.99mA   -15.86mA
-800mV    -16.27mA   -15.52mA   -14.88mA
-530mV    -13.56mA   -12.95mA   -12.57mA
-380mV    -10.33mA   -10.03mA   -9.938mA
300mV     7.984mA    7.783mA    7.776mA
755mV     19.11mA    18.35mA    19.04mA
1.215V    28.11mA    26.43mA    29.39mA
1.49V     31.72mA    29.18mA    34.78mA
1.975V    34.76mA    31.65mA    41.24mA
3V        37.78mA    34.43mA    45.95mA
[GND Clamp]
|   Voltage   I(typ)   I(min)   I(max)
-1.5V     -50.86mA   -48.39mA   -53.31mA
-1.32V    -38.49mA   -36.95mA   -40.31mA
-1.195V   -30.28mA   -29.36mA   -32mA
-1.09V    -23.76mA   -23.33mA   -26.33mA
-950mV    -16.36mA   -16.11mA   -19.5mA
-810mV    -10.64mA   -10.39mA   -13.44mA
-660mV    -5.343mA   -5.541mA   -7.383mA
-550mV    -2.294mA   -2.517mA   -3.532mA
-505mV    -1.389mA   -1.77mA    -2.13mA
-430mV    -374uA     -539.4uA   -960.1uA
-380mV    -171.4uA   -317.5uA   -180.2uA
3V        0A         0A         0A
[Pullup]
|   Voltage   I(typ)   I(min)   I(max)
-1.5V     6.153mA    6.805mA    8.388mA
-1.2V     15.14mA    15.12mA    17.57mA
-1.025V   19.77mA    19.04mA    21.32mA
-950mV    21.3mA     20.21mA    21.45mA
-795mV    21.44mA    20.27mA    20.85mA
-660mV    20.15mA    19.1mA     19.54mA
-505mV    16.8mA     16.28mA    16.93mA
345mV     -10.07mA   -9.849mA   -10.68mA
805mV     -19.63mA   -19.32mA   -22mA
1.055V    -22.71mA   -22.45mA   -26.38mA
1.51V     -25.9mA    -25.71mA   -31.14mA
3V        -31.67mA   -31.54mA   -38.55mA
[POWER Clamp]
|   Voltage   I(typ)   I(min)   I(max)
-1.5V     104.2mA    96.04mA    110.8mA
-1.195V   56.08mA    51.65mA    60.2mA
-1.11V    43.68mA    40.43mA    47.85mA
-1.025V   32.84mA    31.3mA     35.51mA
-950mV    23.76mA    23.64mA    28.1mA
-870mV    17.62mA    17.65mA    20.38mA
-795mV    11.95mA    13.1mA     15.38mA
-665mV    5.081mA    6.451mA    7.641mA
-550mV    1.395mA    1.908mA    2.415mA
-505mV    588.2uA    1.278mA    931.8uA
-315mV    8.745uA    20.93uA    7.341uA
3V        0A         0A         0A
[Ramp]
R_load = 50.00Ohm
|   typ   min   max
dV/dt_r   508.798mV/127.180ps 481.925mV/142.095ps 555.841mV/105.459ps
dV/dt_f   504.967mV/113.872ps 472.002mV/132.514ps 527.439mV/90.594ps
[Falling Waveform]
V_fixture = 1.500V
V_fixture_min = 1.425V
V_fixture_max = 1.575V
R_fixture = 50.00Ohm
|   Time   V(typ)   V(min)   V(max)
0s        1.499V     1.424V     1.574V
75ps      1.499V     1.429V     1.567V
170ps     1.385V     1.354V     1.366V
190ps     1.356V     1.331V     1.278V
245ps     1.174V     1.254V     874.4mV
290ps     938.4mV    1.1V       748.1mV
335ps     777.5mV    910.3mV    718.9mV
370ps     719.1mV    795.2mV    707.4mV
420ps     683.5mV    704.5mV    701.2mV
625ps     657.2mV    637.7mV    695.1mV
[Rising Waveform]
V_fixture = 1.500V
V_fixture_min = 1.425V
V_fixture_max = 1.575V
R_fixture = 50.00Ohm
|   Time   V(typ)   V(min)   V(max)
0s        657.2mV    637.7mV    695.1mV
50ps      684.7mV    651mV      712.6mV
105ps     845.5mV    765.7mV    928.4mV
155ps     933.8mV    868.6mV    1.015V
190ps     1.012V     917.1mV    1.278V
210ps     1.116V     959.6mV    1.429V
245ps     1.33V      1.099V     1.534V
295ps     1.459V     1.32V      1.563V
335ps     1.485V     1.389V     1.568V
625ps     1.499V     1.424V     1.574V
[Rising Waveform]
V_fixture = 0.000V
V_fixture_min = 0.000V
V_fixture_max = 0.000V
R_fixture = 50.00Ohm
|   Time   V(typ)   V(min)   V(max)
0s        250uV      145.9uV    134.6uV
50ps      2.797mV    -3.377mV   4.784mV
165ps     168.6mV    135.2mV    249.9mV
180ps     180.9mV    149.4mV    325.6mV
205ps     222.2mV    169.8mV    541.2mV
230ps     338.3mV    205mV      727.4mV
275ps     600.6mV    378.9mV    870.6mV
330ps     770.3mV    626mV      908.8mV
390ps     825.7mV    746mV      920.1mV
625ps     848.2mV    803.4mV    926.5mV
[Falling Waveform]
V_fixture = 0.000V
V_fixture_min = 0.000V
V_fixture_max = 0.000V
R_fixture = 50.00Ohm
|   Time   V(typ)   V(min)   V(max)
0s        848.2mV    803.4mV    926.5mV
60ps      802.2mV    778.1mV    896.1mV
150ps     590.9mV    620mV      594.2mV
175ps     516.1mV    566.7mV    467.4mV
215ps     342.1mV    460.1mV    156.1mV
245ps     181.5mV    349mV      57.6mV
265ps     103.5mV    258mV      33.37mV
295ps     47.17mV    135.5mV    17.66mV
350ps     15.12mV    36.06mV    8.58mV
625ps     250uV      145.9uV    134.6uV
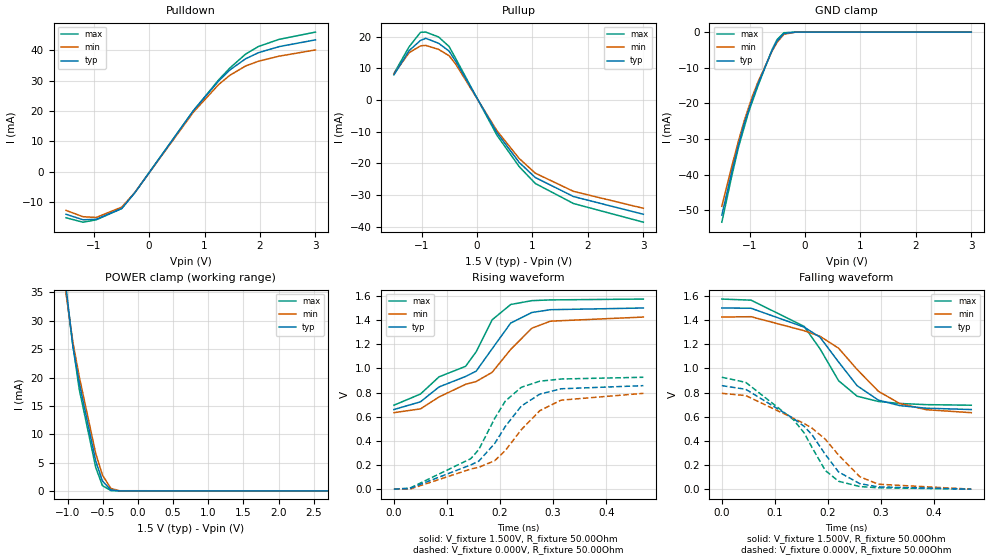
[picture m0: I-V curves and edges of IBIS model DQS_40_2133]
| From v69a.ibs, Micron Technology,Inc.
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| MODEL DQS_40_2133 (40 Ohm Data Strobe I/O with no ODT, 1866/2133 Mbps)
[Model]   DQS_40_2133
Model_type   I/O
Vinl = 625.000mV
Vinh = 875.000mV
Vmeas = 750.000mV
Vref = 750.000mV
Cref = 0.0pF
Rref = 25.000Ohm
|   typ   min   max
C_comp   1.22pF   1.06pF   1.37pF
[Model Spec]
| Input threshold voltage corners
Vinl   0.6250V   0.5875V   0.6625V
Vinh   0.8750V   0.8375V   0.9125V
| Measurement voltage corners
Vmeas   0.7500V   0.7125V   0.7875V
| Timing spec test load voltage corners
Vref   0.7500V   0.7125V   0.7875V
|[Receiver Thresholds]
|Vth   =  0.750V
|Vth_min  =  0.735V
|Vth_max  =  0.765V
|Vinh_ac  =  0.125V
|Vinh_dc  =  0.100V
|Vinl_ac  = -0.125V
|Vinl_dc  = -0.100V
|Tslew_ac =  5.000ns |Not specified, so set to high value
|Threshold_sensitivity = 0.50
|Reference_supply Pullup_ref
[Receiver Thresholds]
Vcross_low   = 0.625V
Vcross_high  = 0.875V
Vdiff_ac   = 250mV
Vdiff_dc   = 200mV
Tdiffslew_ac = 10.000ns |Not specified, so set to high value
[Voltage Range]   1.5000V   1.4250V   1.5750V
[Pullup Reference]   1.5000V   1.4250V   1.5750V
| Junction Temperature (Ambient temp is 35C typ, 95C min, 0C max)
[Temperature Range]   50.0   110.0   0.0
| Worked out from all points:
|   slope of the pulldown table from 0 to 0.225 V, typ, clamps not added: 38 ohm
|   slope of the pullup table from 0 to 0.225 V, typ, clamps not added: 33.9 ohm
|   GND clamp passes 1 mA (typ) near -0.42 V on its own axis
|   POWER clamp passes 1 mA (typ) near -0.46 V on its own axis
|   falling waveform, V_fixture 1.500V, R_fixture 50.00Ohm: 20-80 % time 101ps typ, 116ps min, 91.5ps max; typ from 1.5 V to 0.659 V
|   rising waveform, V_fixture 1.500V, R_fixture 50.00Ohm: 20-80 % time 132ps typ, 147ps min, 117ps max; typ from 0.659 V to 1.5 V
|   rising waveform, V_fixture 0.000V, R_fixture 50.00Ohm: 20-80 % time 121ps typ, 135ps min, 108ps max; typ from 0 V to 0.857 V
|   falling waveform, V_fixture 0.000V, R_fixture 50.00Ohm: 20-80 % time 118ps typ, 131ps min, 107ps max; typ from 0.857 V to 0 V
[Pulldown]
|   Voltage   I(typ)   I(min)   I(max)
-1.5V     -13.96mA   -12.69mA   -15.12mA
-1.195V   -15.78mA   -14.77mA   -16.58mA
-955mV    -15.63mA   -15.03mA   -15.81mA
-495mV    -12.08mA   -11.62mA   -12.1mA
-260mV    -6.957mA   -6.872mA   -6.856mA
800mV     20.15mA    19.66mA    20.12mA
1.255V    29.89mA    28.72mA    30.25mA
1.455V    33.47mA    31.73mA    34.11mA
1.74V     37.18mA    34.8mA     38.71mA
1.975V    39.19mA    36.38mA    41.24mA
2.35V     41.19mA    38.05mA    43.59mA
3V        43.39mA    40.08mA    45.95mA
[GND Clamp]
|   Voltage   I(typ)   I(min)   I(max)
-1.5V     -51.33mA   -48.85mA   -53.31mA
-1.32V    -39.2mA    -37.62mA   -40.31mA
-1.2V     -31.7mA    -30.57mA   -32.31mA
-1.1V     -25.85mA   -25.09mA   -26.87mA
-1.02V    -22.1mA    -21.32mA   -22.57mA
-950mV    -18.82mA   -18.03mA   -19.5mA
-850mV    -14.61mA   -14.07mA   -15.14mA
-595mV    -5.207mA   -5.394mA   -4.943mA
-505mV    -2.544mA   -2.91mA    -2.13mA
-380mV    -419.6uA   -621.5uA   -180.2uA
-165mV    0A         -2.918uA   0A
3V        0A         0A         0A
[Pullup]
|   Voltage   I(typ)   I(min)   I(max)
-1.5V     7.95mA     8.248mA    8.388mA
-1.225V   15.63mA    14.98mA    16.85mA
-1.02V    18.85mA    17.12mA    21.4mA
-925mV    19.5mA     17.26mA    21.47mA
-695mV    17.95mA    16.02mA    19.94mA
-505mV    15.48mA    14.01mA    16.93mA
-385mV    12.25mA    11.36mA    13.11mA
360mV     -10.33mA   -9.71mA    -11.13mA
760mV     -19.68mA   -18.43mA   -21mA
1.05V     -24.45mA   -23.07mA   -26.32mA
1.74V     -30.46mA   -28.82mA   -32.66mA
3V        -36.05mA   -34.16mA   -38.55mA
[POWER Clamp]
|   Voltage   I(typ)   I(min)   I(max)
-1.5V     104.9mA    96.95mA    110.8mA
-1.37V    84.07mA    77.64mA    88.84mA
-1.225V   61.86mA    57.37mA    65.04mA
-1.105V   44.83mA    42.59mA    47.13mA
-1.02V    35.67mA    34.63mA    34.86mA
-925mV    25.54mA    26.27mA    25.68mA
-835mV    19.09mA    20.2mA     17.96mA
-600mV    5.255mA    6.588mA    4.139mA
-505mV    1.75mA     2.798mA    931.8uA
-385mV    169.1uA    435.8uA    68.05uA
-260mV    8.657uA    35.03uA    111.5nA
3V        0A         0A         0A
[Ramp]
R_load = 50.00Ohm
|   typ   min   max
dV/dt_r   514.194mV/120.855ps 475.954mV/134.815ps 555.841mV/107.599ps
dV/dt_f   504.129mV/101.355ps 474.729mV/116.386ps 527.439mV/91.470ps
[Falling Waveform]
V_fixture = 1.500V
V_fixture_min = 1.425V
V_fixture_max = 1.575V
R_fixture = 50.00Ohm
|   Time   V(typ)   V(min)   V(max)
0s        1.5V       1.425V     1.574V
55ps      1.498V     1.428V     1.565V
155ps     1.342V     1.312V     1.348V
185ps     1.258V     1.266V     1.162V
220ps     1.053V     1.167V     898mV
255ps     856.3mV    990.5mV    769.5mV
295ps     737.3mV    810.5mV    726.1mV
335ps     691.9mV    709.7mV    709.7mV
385ps     670.6mV    658mV      699.9mV
470ps     659.3mV    633.4mV    695.1mV
[Rising Waveform]
V_fixture = 1.500V
V_fixture_min = 1.425V
V_fixture_max = 1.575V
R_fixture = 50.00Ohm
|   Time   V(typ)   V(min)   V(max)
0s        659.3mV    633.4mV    695.1mV
50ps      723.3mV    664.7mV    787.6mV
85ps      846.4mV    763.4mV    930mV
135ps     933.1mV    868.1mV    1.017V
155ps     977.4mV    891.5mV    1.138V
185ps     1.162V     967.2mV    1.402V
220ps     1.375V     1.157V     1.529V
260ps     1.463V     1.333V     1.561V
295ps     1.486V     1.391V     1.567V
470ps     1.5V       1.425V     1.574V
[Rising Waveform]
V_fixture = 0.000V
V_fixture_min = 0.000V
V_fixture_max = 0.000V
R_fixture = 50.00Ohm
|   Time   V(typ)   V(min)   V(max)
0s        80.86uV    127.7uV    134.6uV
30ps      6.217mV    432.3uV    8.456mV
145ps     201.3mV    167.2mV    253.1mV
160ps     232.3mV    181.1mV    328.8mV
190ps     378.9mV    236.2mV    586.7mV
210ps     520.1mV    320.1mV    729.9mV
240ps     688.2mV    492.9mV    843.6mV
275ps     787.1mV    650.2mV    894.2mV
315ps     831.3mV    737.1mV    912.2mV
470ps     857.1mV    793.4mV    926.5mV
[Falling Waveform]
V_fixture = 0.000V
V_fixture_min = 0.000V
V_fixture_max = 0.000V
R_fixture = 50.00Ohm
|   Time   V(typ)   V(min)   V(max)
0s        857.1mV    793.4mV    926.5mV
45ps      827.1mV    775mV      884.6mV
135ps     585.3mV    586.6mV    574.8mV
155ps     520.4mV    543.7mV    466.8mV
170ps     450.4mV    505.2mV    344.8mV
195ps     287.5mV    413.3mV    154.7mV
220ps     142.4mV    282.3mV    65.42mV
260ps     45.54mV    103.1mV    21.62mV
295ps     19.05mV    40.92mV    11.55mV
470ps     80.86uV    127.7uV    134.6uV
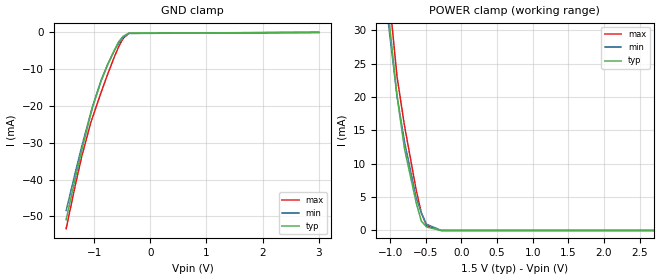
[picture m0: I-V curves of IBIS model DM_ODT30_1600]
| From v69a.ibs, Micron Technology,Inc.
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| MODEL DM_ODT30_1600 (DM Input Model with 30ohm ODT, 1600Mbps)
[Model]   DM_ODT30_1600
Model_type   Input
Vinl = 600.000mV
Vinh = 900.000mV
|   typ   min   max
C_comp   1.22pF   1.07pF   1.39pF
| Note: C_comp changes when the ODT circuit is enabled.
[Model Spec]
| Input threshold voltage corners
Vinl   0.6000V   0.5625V   0.6375V
Vinh   0.9000V   0.8625V   0.9375V
[Receiver Thresholds]
Vth   =  0.750V
Vth_min  =  0.735V
Vth_max  =  0.765V
Vinh_ac  =  0.150V
Vinh_dc  =  0.100V
Vinl_ac  = -0.150V
Vinl_dc  = -0.100V
Tslew_ac =  5.000ns |Not specified, so set to high value
[Voltage Range]   1.5000V   1.4250V   1.5750V
| Junction Temperature (Ambient temp is 35C typ, 95C min, 0C max)
[Temperature Range]   50.0   110.0   0.0
[Add Submodel]
| Submodel Name   Mode
30ohm_ODT_1600   Non-Driving
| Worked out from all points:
|   GND clamp passes 1 mA (typ) near -0.48 V on its own axis
|   POWER clamp passes 1 mA (typ) near -0.53 V on its own axis
[GND Clamp]
|   Voltage   I(typ)   I(min)   I(max)
-1.5V     -50.86mA   -48.39mA   -53.31mA
-1.335V   -39.51mA   -37.89mA   -41.36mA
-1.22V    -31.91mA   -30.85mA   -33.59mA
-1.06V    -22.14mA   -21.75mA   -24.46mA
-1.03V    -20.37mA   -20.11mA   -23.1mA
-875mV    -13.13mA   -12.88mA   -16.2mA
-765mV    -8.986mA   -8.82mA    -11.56mA
-635mV    -4.662mA   -4.732mA   -6.435mA
-565mV    -2.562mA   -2.983mA   -3.942mA
-485mV    -1.053mA   -1.384mA   -1.64mA
-380mV    -208.9uA   -292.7uA   -211uA
3V        0A         0A         0A
[POWER Clamp]
|   Voltage   I(typ)   I(min)   I(max)
-1.5V     104.2mA    96.04mA    110.8mA
-1.22V    59.88mA    55.04mA    64.17mA
-1.155V   50.11mA    46.13mA    54.38mA
-1.06V    36.99mA    35.03mA    40.06mA
-1.025V   32.28mA    30.95mA    36.2mA
-905mV    20.23mA    20.1mA     23.06mA
-800mV    12.24mA    13.34mA    15.7mA
-635mV    4.119mA    4.874mA    6.02mA
-565mV    1.438mA    2.643mA    2.719mA
-490mV    520.5uA    937.2uA    712uA
-285mV    1.423uA    9.711uA    221nA
3V        0A         0A         0A
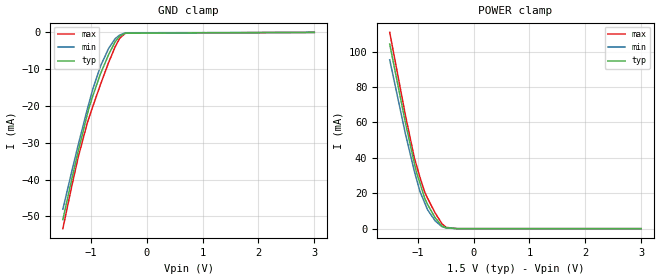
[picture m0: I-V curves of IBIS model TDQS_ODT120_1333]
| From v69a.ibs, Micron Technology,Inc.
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| MODEL TDQS_ODT120_1333 (Termination Model with 120ohm ODT, 1333Mbps)
[Model]   TDQS_ODT120_1333
Model_type   Terminator
|   typ   min   max
C_comp   1.24pF   1.10pF   1.39pF
| Note: C_comp changes when the ODT circuit is enabled.
[Voltage Range]   1.5000V   1.4250V   1.5750V
| Junction Temperature (Ambient temp is 35C typ, 95C min, 0C max)
[Temperature Range]   50.0   110.0   0.0
[Add Submodel]
| Submodel Name   Mode
120ohm_ODT_1333   Non-Driving
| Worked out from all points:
|   GND clamp passes 1 mA (typ) near -0.48 V on its own axis
|   POWER clamp passes 1 mA (typ) near -0.53 V on its own axis
[GND Clamp]
|   Voltage   I(typ)   I(min)   I(max)
-1.5V     -50.86mA   -48.03mA   -53.31mA
-1.335V   -39.51mA   -37.41mA   -41.36mA
-1.22V    -31.91mA   -30.23mA   -33.59mA
-1.06V    -22.14mA   -20.74mA   -24.46mA
-1.03V    -20.37mA   -19.08mA   -23.1mA
-960mV    -17.09mA   -15.22mA   -19.96mA
-825mV    -11.18mA   -9.113mA   -14.07mA
-680mV    -6.012mA   -4.321mA   -8.138mA
-565mV    -2.562mA   -1.714mA   -3.942mA
-485mV    -1.053mA   -743.8uA   -1.64mA
-380mV    -208.9uA   -97.58uA   -211uA
3V        0A         0A         0A
[POWER Clamp]
|   Voltage   I(typ)   I(min)   I(max)
-1.5V     104.2mA    95.33mA    110.8mA
-1.22V    59.88mA    53.65mA    64.17mA
-1.06V    36.99mA    32.51mA    40.06mA
-1.025V   32.28mA    28.5mA     36.2mA
-960mV    25.75mA    21.1mA     29.08mA
-875mV    17.23mA    14.62mA    20.76mA
-825mV    13.81mA    10.81mA    17.3mA
-690mV    6.286mA    4.503mA    9.027mA
-565mV    1.438mA    1.112mA    2.719mA
-490mV    520.5uA    387uA      712uA
-290mV    1.769uA    1.056uA    286.1nA
3V        0A         0A         0A
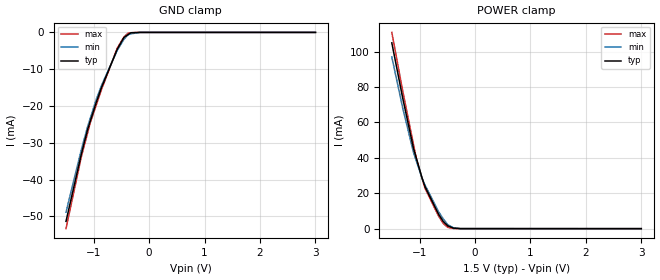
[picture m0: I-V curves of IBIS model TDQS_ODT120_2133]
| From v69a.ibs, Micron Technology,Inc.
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| MODEL TDQS_ODT120_2133 (Termination Model with 120ohm ODT, 1866/2133 Mbps)
[Model]   TDQS_ODT120_2133
Model_type   Terminator
|   typ   min   max
C_comp   1.20pF   1.05pF   1.36pF
| Note: C_comp changes when the ODT circuit is enabled.
[Voltage Range]   1.5000V   1.4250V   1.5750V
| Junction Temperature (Ambient temp is 35C typ, 95C min, 0C max)
[Temperature Range]   50.0   110.0   0.0
[Add Submodel]
| Submodel Name   Mode
120ohm_ODT_2133   Non-Driving
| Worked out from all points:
|   GND clamp passes 1 mA (typ) near -0.42 V on its own axis
|   POWER clamp passes 1 mA (typ) near -0.47 V on its own axis
[GND Clamp]
|   Voltage   I(typ)   I(min)   I(max)
-1.5V     -51.33mA   -48.85mA   -53.31mA
-1.225V   -33.17mA   -31.96mA   -33.91mA
-1.11V    -26.38mA   -25.59mA   -27.31mA
-1.06V    -24mA      -23.21mA   -24.46mA
-955mV    -19.04mA   -18.24mA   -19.74mA
-855mV    -14.8mA    -14.26mA   -15.35mA
-575mV    -4.569mA   -4.842mA   -4.255mA
-455mV    -1.373mA   -1.876mA   -1.232mA
-380mV    -600.5uA   -637.3uA   -211uA
-330mV    -105.7uA   -382.3uA   -79.03uA
-165mV    -2.061uA   -3.044uA   0A
3V        0A         0A         0A
[POWER Clamp]
|   Voltage   I(typ)   I(min)   I(max)
-1.5V     104.9mA    96.95mA    110.8mA
-1.305V   73.96mA    68.35mA    78.05mA
-1.11V    45.47mA    43.15mA    47.59mA
-1.06V    40.01mA    38.39mA    40.06mA
-955mV    28.63mA    28.51mA    28.54mA
-905mV    24.01mA    24.84mA    23.06mA
-660mV    8.35mA     9.771mA    7.255mA
-570mV    3.953mA    5.39mA     2.853mA
-490mV    1.557mA    2.191mA    712uA
-385mV    314.2uA    439.4uA    73.92uA
-265mV    10.67uA    38.19uA    0A
3V        0A         0A         0A
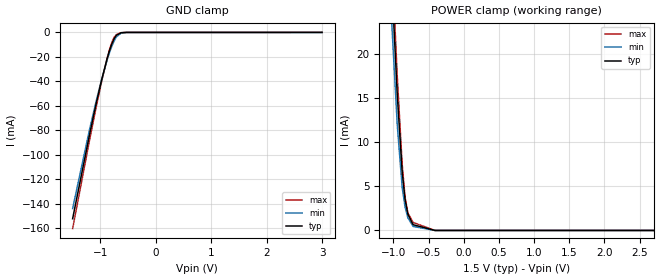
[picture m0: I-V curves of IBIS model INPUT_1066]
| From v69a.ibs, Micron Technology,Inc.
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| MODEL INPUT_1066 (Address/Command/Control Input Model, 800/1066Mbps)
[Model]   INPUT_1066
Model_type   Input
Vinl = 575.000mV
Vinh = 925.000mV
|   typ   min   max
C_comp   0.65pF   0.55pF   0.76pF
[Model Spec]
| Input threshold voltage corners
Vinl   0.5750V   0.5375V   0.6125V
Vinh   0.9250V   0.8875V   0.9625V
[Receiver Thresholds]
Vth   =  0.750V
Vth_min  =  0.735V
Vth_max  =  0.765V
Vinh_ac  =  0.175V
Vinh_dc  =  0.100V
Vinl_ac  = -0.175V
Vinl_dc  = -0.100V
Tslew_ac =  10.00ns |Not specified, so set to high value
[Voltage Range]   1.5000V   1.4250V   1.5750V
| Junction Temperature (Ambient temp is 35C typ, 95C min, 0C max)
[Temperature Range]   50.0   110.0   0.0
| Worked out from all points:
|   GND clamp passes 1 mA (typ) near -0.67 V on its own axis
|   POWER clamp passes 1 mA (typ) near -0.75 V on its own axis
[GND Clamp]
|   Voltage   I(typ)   I(min)   I(max)
-1.5V     -152.2mA   -143.9mA   -160.3mA
-1.195V   -83.57mA   -79.41mA   -88.17mA
-1.075V   -58.14mA   -56.11mA   -61.05mA
-980mV    -39.42mA   -39.09mA   -40.73mA
-875mV    -21.01mA   -22.22mA   -20.55mA
-830mV    -14.22mA   -15.9mA    -13.26mA
-790mV    -9.108mA   -10.99mA   -7.847mA
-750mV    -5.075mA   -6.811mA   -3.982mA
-710mV    -2.343mA   -3.596mA   -1.761mA
-625mV    -287.8uA   -542.9uA   -221.3uA
-530mV    -17.93uA   -50.22uA   -11.23uA
3V        0A         0A         0A
[POWER Clamp]
|   Voltage   I(typ)   I(min)   I(max)
-1.5V     121.2mA    112.6mA    127.2mA
-1.095V   40.89mA    35.16mA    44.47mA
-1.07V    36.29mA    30.86mA    39.66mA
-1.055V   33.59mA    28.33mA    36.82mA
-1.045V   31.8mA     26.69mA    34.93mA
-945mV    15.35mA    11.95mA    17.45mA
-875mV    6.616mA    4.853mA    7.478mA
-835mV    3.57mA     2.696mA    3.835mA
-795mV    1.862mA    1.445mA    1.991mA
-720mV    654.7uA    459.8uA    910.6uA
-410mV    3.061uA    1.636uA    8.872uA
3V        0A         0A         0A
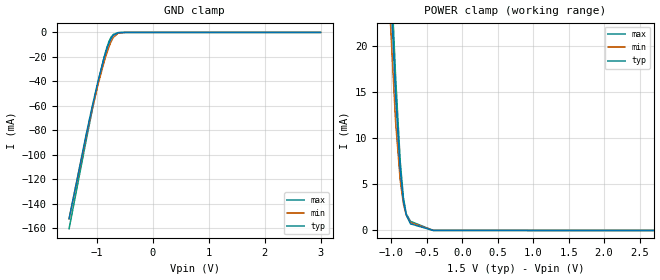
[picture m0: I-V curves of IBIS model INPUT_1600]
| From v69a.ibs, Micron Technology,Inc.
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| MODEL INPUT_1600 (Address/Command/Control Input Model, 1600Mbps)
[Model]   INPUT_1600
Model_type   Input
Vinl = 600.000mV
Vinh = 900.000mV
|   typ   min   max
C_comp   0.63pF   0.53pF   0.73pF
[Model Spec]
| Input threshold voltage corners
Vinl   0.6000V   0.5625V   0.6375V
Vinh   0.9000V   0.8625V   0.9375V
[Receiver Thresholds]
Vth   =  0.750V
Vth_min  =  0.735V
Vth_max  =  0.765V
Vinh_ac  =  0.150V
Vinh_dc  =  0.100V
Vinl_ac  = -0.150V
Vinl_dc  = -0.100V
Tslew_ac =  10.00ns |Not specified, so set to high value
[Voltage Range]   1.5000V   1.4250V   1.5750V
| Junction Temperature (Ambient temp is 35C typ, 95C min, 0C max)
[Temperature Range]   50.0   110.0   0.0
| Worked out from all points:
|   GND clamp passes 1 mA (typ) near -0.67 V on its own axis
|   POWER clamp passes 1 mA (typ) near -0.75 V on its own axis
[GND Clamp]
|   Voltage   I(typ)   I(min)   I(max)
-1.5V     -152.2mA   -152.2mA   -160.3mA
-1.195V   -83.57mA   -84.89mA   -88.17mA
-1.09V    -61.23mA   -63.26mA   -64.37mA
-980mV    -39.42mA   -42.22mA   -40.73mA
-875mV    -21.01mA   -24.3mA    -20.55mA
-830mV    -14.22mA   -17.55mA   -13.26mA
-790mV    -9.108mA   -12.26mA   -7.847mA
-750mV    -5.075mA   -7.616mA   -3.982mA
-710mV    -2.343mA   -4.146mA   -1.761mA
-625mV    -287.8uA   -738.9uA   -221.3uA
-505mV    -8.053uA   -42.81uA   -5.048uA
3V        0A         0A         0A
[POWER Clamp]
|   Voltage   I(typ)   I(min)   I(max)
-1.5V     121.2mA    114.2mA    127.2mA
-1.09V    39.96mA    34.96mA    43.5mA
-1.07V    36.29mA    31.5mA     39.66mA
-1.055V   33.59mA    28.95mA    36.82mA
-1.045V   31.8mA     27.29mA    34.93mA
-940mV    14.59mA    11.76mA    16.63mA
-875mV    6.616mA    5.443mA    7.478mA
-830mV    3.216mA    2.88mA     3.545mA
-790mV    1.706mA    1.661mA    1.793mA
-730mV    716uA      851uA      984.8uA
-410mV    3.061uA    11.47uA    8.872uA
3V        0A         0A         0A
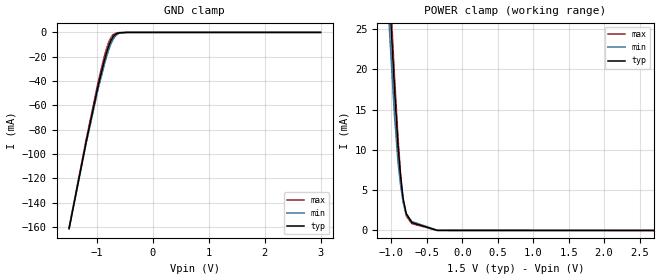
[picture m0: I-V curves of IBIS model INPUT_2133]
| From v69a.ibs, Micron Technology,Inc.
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| MODEL INPUT_2133 (Address/Command/Control Input Model, 1866/2133 Mbps)
[Model]   INPUT_2133
Model_type   Input
Vinl = 625.000mV
Vinh = 875.000mV
|   typ   min   max
C_comp   0.62pF   0.52pF   0.72pF
[Model Spec]
| Input threshold voltage corners
Vinl   0.6250V   0.5875V   0.6625V
Vinh   0.8750V   0.8375V   0.9125V
[Receiver Thresholds]
Vth   =  0.750V
Vth_min  =  0.735V
Vth_max  =  0.765V
Vinh_ac  =  0.125V
Vinh_dc  =  0.100V
Vinl_ac  = -0.125V
Vinl_dc  = -0.100V
Tslew_ac =  10.00ns |Not specified, so set to high value
[Voltage Range]   1.5000V   1.4250V   1.5750V
| Junction Temperature (Ambient temp is 35C typ, 95C min, 0C max)
[Temperature Range]   50.0   110.0   0.0
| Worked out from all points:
|   GND clamp passes 1 mA (typ) near -0.65 V on its own axis
|   POWER clamp passes 1 mA (typ) near -0.71 V on its own axis
[GND Clamp]
|   Voltage   I(typ)   I(min)   I(max)
-1.5V     -161.5mA   -161.4mA   -160.3mA
-1.19V    -89.12mA   -90.38mA   -87.02mA
-980mV    -43.85mA   -46.51mA   -40.73mA
-875mV    -24.16mA   -27.37mA   -20.55mA
-830mV    -16.78mA   -20.1mA    -13.26mA
-790mV    -11.11mA   -14.23mA   -7.847mA
-750mV    -6.538mA   -9.216mA   -3.982mA
-710mV    -3.315mA   -5.419mA   -1.761mA
-660mV    -1.274mA   -2.336mA   -555.3uA
-605mV    -342.2uA   -819.9uA   -113.9uA
-475mV    -10.68uA   -44.62uA   -1.393uA
3V        0A         0A         0A
[POWER Clamp]
|   Voltage   I(typ)   I(min)   I(max)
-1.5V     123mA      115.9mA    127.2mA
-1.06V    35.21mA    30.51mA    37.77mA
-1.035V   30.7mA     26.31mA    33.07mA
-1.02V    28.06mA    23.88mA    30.32mA
-955mV    17.44mA    14.21mA    19.08mA
-905mV    10.38mA    8.403mA    11.48mA
-870mV    6.817mA    5.632mA    6.993mA
-835mV    4.025mA    3.535mA    3.835mA
-790mV    2.097mA    2.041mA    1.793mA
-710mV    974.4uA    1.106mA    841.6uA
-350mV    7.306uA    20.43uA    2.118uA
3V        0A         0A         0A
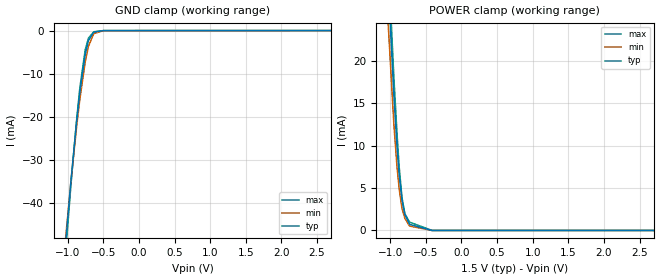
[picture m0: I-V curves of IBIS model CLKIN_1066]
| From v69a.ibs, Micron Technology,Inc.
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| MODEL CLKIN_1066 (Clock Input Model Datarate, 800/1066Mbps)
[Model]   CLKIN_1066
Model_type   Input
Vinl = 575.000mV
Vinh = 925.000mV
|   typ   min   max
C_comp   0.66pF   0.60pF   0.71pF
[Model Spec]
| Input threshold voltage corners
Vinl   0.5750V   0.5375V   0.6125V
Vinh   0.9250V   0.8875V   0.9625V
|[Receiver Thresholds]
|Vth   =  0.750V
|Vth_min  =  0.735V
|Vth_max  =  0.765V
|Vinh_ac  =  0.175V
|Vinh_dc  =  0.100V
|Vinl_ac  = -0.175V
|Vinl_dc  = -0.100V
|Tslew_ac =  10.00ns |Not specified, so set to high value
[Receiver Thresholds]
Vcross_low   = 0.575V
Vcross_high  = 0.925V
Vdiff_ac   = 350mV
Vdiff_dc   = 200mV
Tdiffslew_ac = 10.000ns |Not specified, so set to high value
[Voltage Range]   1.5000V   1.4250V   1.5750V
| Junction Temperature (Ambient temp is 35C typ, 95C min, 0C max)
[Temperature Range]   50.0   110.0   0.0
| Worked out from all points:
|   GND clamp passes 1 mA (typ) near -0.67 V on its own axis
|   POWER clamp passes 1 mA (typ) near -0.75 V on its own axis
[GND Clamp]
|   Voltage   I(typ)   I(min)   I(max)
-1.5V     -152.3mA   -143.9mA   -160.4mA
-1.315V   -110.1mA   -104.2mA   -116.2mA
-1.18V    -80.29mA   -76.4mA    -84.76mA
-1.06V    -55.09mA   -53.33mA   -57.76mA
-955mV    -34.79mA   -34.87mA   -35.65mA
-875mV    -21.01mA   -22.23mA   -20.55mA
-830mV    -14.23mA   -15.87mA   -13.26mA
-755mV    -5.507mA   -7.288mA   -4.441mA
-710mV    -2.342mA   -3.653mA   -1.775mA
-635mV    -354.9uA   -701.3uA   -277.7uA
-500mV    -6.788uA   -21.82uA   -3.444uA
3V        0A         0A         0A
[POWER Clamp]
|   Voltage   I(typ)   I(min)   I(max)
-1.5V     121.2mA    112.6mA    127.2mA
-1.095V   40.89mA    35.15mA    44.47mA
-1.06V    34.48mA    29.17mA    37.76mA
-1.045V   31.8mA     26.68mA    34.93mA
-950mV    16.07mA    12.58mA    18.13mA
-905mV    9.877mA    7.462mA    11.4mA
-875mV    6.603mA    4.896mA    7.482mA
-835mV    3.579mA    2.565mA    3.829mA
-795mV    1.862mA    1.435mA    1.973mA
-730mV    717.2uA    525.1uA    985uA
-415mV    3.343uA    2.093uA    10.12uA
3V        0A         0A         0A
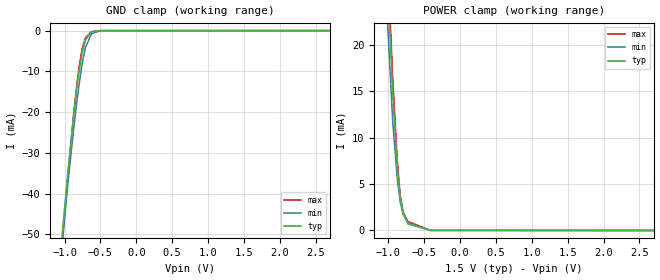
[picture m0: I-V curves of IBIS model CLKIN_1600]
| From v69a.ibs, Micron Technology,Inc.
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| MODEL CLKIN_1600 (Clock Input Model Datarate, 1600Mbps)
[Model]   CLKIN_1600
Model_type   Input
Vinl = 600.000mV
Vinh = 900.000mV
|   typ   min   max
C_comp   0.63pF   0.58pF   0.68pF
[Model Spec]
| Input threshold voltage corners
Vinl   0.6000V   0.5625V   0.6375V
Vinh   0.9000V   0.8625V   0.9375V
|[Receiver Thresholds]
|Vth   =  0.750V
|Vth_min  =  0.735V
|Vth_max  =  0.765V
|Vinh_ac  =  0.150V
|Vinh_dc  =  0.100V
|Vinl_ac  = -0.150V
|Vinl_dc  = -0.100V
|Tslew_ac =  10.00ns |Not specified, so set to high value
[Receiver Thresholds]
Vcross_low   = 0.600V
Vcross_high  = 0.900V
Vdiff_ac   = 300mV
Vdiff_dc   = 200mV
Tdiffslew_ac = 10.000ns |Not specified, so set to high value
[Voltage Range]   1.5000V   1.4250V   1.5750V
| Junction Temperature (Ambient temp is 35C typ, 95C min, 0C max)
[Temperature Range]   50.0   110.0   0.0
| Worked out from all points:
|   GND clamp passes 1 mA (typ) near -0.67 V on its own axis
|   POWER clamp passes 1 mA (typ) near -0.75 V on its own axis
[GND Clamp]
|   Voltage   I(typ)   I(min)   I(max)
-1.5V     -152.3mA   -152.3mA   -160.4mA
-1.2V     -84.65mA   -85.95mA   -89.35mA
-1.06V    -55.09mA   -57.34mA   -57.76mA
-955mV    -34.79mA   -37.72mA   -35.65mA
-875mV    -21.01mA   -24.3mA    -20.55mA
-830mV    -14.23mA   -17.56mA   -13.26mA
-790mV    -9.112mA   -12.25mA   -7.868mA
-755mV    -5.507mA   -8.107mA   -4.441mA
-710mV    -2.342mA   -4.189mA   -1.775mA
-625mV    -287.2uA   -768.3uA   -221.7uA
-500mV    -6.788uA   -37.24uA   -3.444uA
3V        0A         0A         0A
[POWER Clamp]
|   Voltage   I(typ)   I(min)   I(max)
-1.5V     121.2mA    114.2mA    127.2mA
-1.105V   42.75mA    37.61mA    46.41mA
-1.085V   39.04mA    34.09mA    42.54mA
-1.06V    34.48mA    29.79mA    37.76mA
-1.045V   31.8mA     27.28mA    34.93mA
-940mV    14.69mA    11.77mA    16.57mA
-875mV    6.603mA    5.448mA    7.482mA
-835mV    3.579mA    3.086mA    3.829mA
-795mV    1.862mA    1.735mA    1.973mA
-730mV    717.2uA    849.4uA    985uA
-415mV    3.343uA    12.84uA    10.12uA
3V        0A         0A         0A
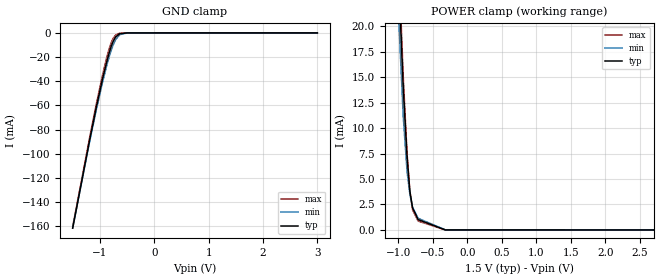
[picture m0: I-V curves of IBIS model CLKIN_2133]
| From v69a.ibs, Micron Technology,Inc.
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| MODEL CLKIN_2133 (Clock Input Model Datarate, 1866/2133 Mbps)
[Model]   CLKIN_2133
Model_type   Input
Vinl = 625.000mV
Vinh = 875.000mV
|   typ   min   max
C_comp   0.62pF   0.57pF   0.67pF
[Model Spec]
| Input threshold voltage corners
Vinl   0.6250V   0.5875V   0.6625V
Vinh   0.8750V   0.8375V   0.9125V
|[Receiver Thresholds]
|Vth   =  0.750V
|Vth_min  =  0.735V
|Vth_max  =  0.765V
|Vinh_ac  =  0.125V
|Vinh_dc  =  0.100V
|Vinl_ac  = -0.125V
|Vinl_dc  = -0.100V
|Tslew_ac =  10.00ns |Not specified, so set to high value
[Receiver Thresholds]
Vcross_low   = 0.625V
Vcross_high  = 0.875V
Vdiff_ac   = 250mV
Vdiff_dc   = 200mV
Tdiffslew_ac = 10.000ns |Not specified, so set to high value
[Voltage Range]   1.5000V   1.4250V   1.5750V
| Junction Temperature (Ambient temp is 35C typ, 95C min, 0C max)
[Temperature Range]   50.0   110.0   0.0
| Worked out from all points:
|   GND clamp passes 1 mA (typ) near -0.65 V on its own axis
|   POWER clamp passes 1 mA (typ) near -0.71 V on its own axis
[GND Clamp]
|   Voltage   I(typ)   I(min)   I(max)
-1.5V     -161.6mA   -161.5mA   -160.4mA
-1.185V   -87.98mA   -89.27mA   -85.9mA
-1.065V   -61.48mA   -63.55mA   -58.85mA
-955mV    -38.87mA   -41.72mA   -35.65mA
-875mV    -24.12mA   -27.27mA   -20.55mA
-830mV    -16.7mA    -20.03mA   -13.26mA
-790mV    -10.97mA   -14.28mA   -7.868mA
-755mV    -7.004mA   -9.937mA   -4.441mA
-710mV    -3.297mA   -5.548mA   -1.775mA
-635mV    -738.4uA   -1.474mA   -277.7uA
-500mV    -21.09uA   -79.77uA   -3.444uA
3V        0A         0A         0A
[POWER Clamp]
|   Voltage   I(typ)   I(min)   I(max)
-1.5V     123mA      115.9mA    127.2mA
-1.09V    40.76mA    35.72mA    43.51mA
-1.075V   37.97mA    33.09mA    40.62mA
-1.055V   34.31mA    29.67mA    36.81mA
-1.04V    31.59mA    27.19mA    34mA
-930mV    13.88mA    11.08mA    15.01mA
-875mV    7.194mA    5.75mA     7.482mA
-835mV    3.828mA    3.547mA    3.829mA
-795mV    2.164mA    2.224mA    1.973mA
-715mV    1.016mA    1.145mA    871.4uA
-320mV    2.968uA    11.59uA    244.8nA
3V        0A         0A         0A
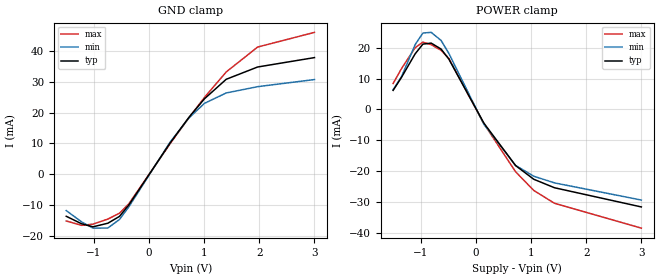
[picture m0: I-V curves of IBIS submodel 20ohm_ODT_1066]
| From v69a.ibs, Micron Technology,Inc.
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|   SUBMODEL 20ohm_ODT_1066
[Submodel]  20ohm_ODT_1066
Submodel_type   Dynamic_clamp
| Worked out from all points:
|   POWER clamp passes 1 mA (typ) near -0.03 V on its own axis
[GND Clamp]
|   Voltage   I(typ)   I(min)   I(max)
-1.5V     -13.6mA    -11.75mA   -15.12mA
-1.22V    -16.04mA   -15.43mA   -16.54mA
-1.015V   -17.01mA   -17.44mA   -16.15mA
-745mV    -15.85mA   -17.4mA    -14.5mA
-535mV    -13.64mA   -14.63mA   -12.61mA
-365mV    -9.926mA   -10.54mA   -9.564mA
385mV     10.19mA    10.45mA    9.946mA
720mV     18.33mA    18.15mA    18.22mA
1.005V    24.43mA    22.96mA    24.86mA
1.4V      30.76mA    26.33mA    33.13mA
1.97V     34.74mA    28.37mA    41.2mA
3V        37.78mA    30.67mA    45.95mA
[POWER Clamp]
|   Voltage   I(typ)   I(min)   I(max)
-1.5V     6.153mA    6.385mA    8.388mA
-1.35V    10.33mA    10.52mA    13.16mA
-1.1V     18.03mA    21.02mA    20.03mA
-960mV    21.17mA    24.77mA    21.81mA
-810mV    21.5mA     24.98mA    20.98mA
-630mV    19.56mA    22.35mA    19.15mA
-490mV    16.32mA    18.17mA    16.52mA
145mV     -4.456mA   -4.817mA   -4.637mA
720mV     -18.25mA   -18.2mA    -20.25mA
1.05V     -22.69mA   -21.71mA   -26.32mA
1.425V    -25.44mA   -23.86mA   -30.48mA
3V        -31.67mA   -29.44mA   -38.55mA
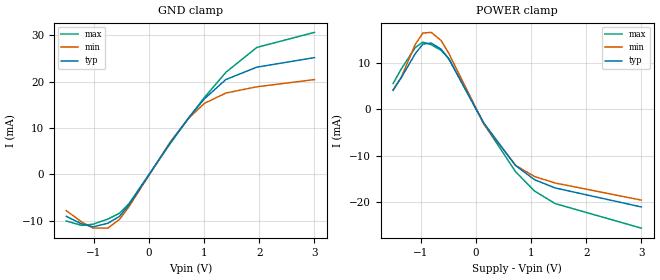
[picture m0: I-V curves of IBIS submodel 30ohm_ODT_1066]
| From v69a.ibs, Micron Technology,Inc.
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|   SUBMODEL 30ohm_ODT_1066
[Submodel]  30ohm_ODT_1066
Submodel_type   Dynamic_clamp
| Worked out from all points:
|   POWER clamp passes 1 mA (typ) near -0.05 V on its own axis
[GND Clamp]
|   Voltage   I(typ)   I(min)   I(max)
-1.5V     -9.065mA   -7.836mA   -10.08mA
-1.22V    -10.7mA    -10.29mA   -11.03mA
-1.015V   -11.34mA   -11.62mA   -10.77mA
-745mV    -10.57mA   -11.6mA    -9.668mA
-535mV    -9.093mA   -9.751mA   -8.409mA
-365mV    -6.617mA   -7.024mA   -6.376mA
385mV     6.793mA    6.969mA    6.631mA
725mV     12.29mA    12.17mA    12.23mA
1.005V    16.29mA    15.31mA    16.58mA
1.395V    20.47mA    17.54mA    22.02mA
1.955V    23.12mA    18.88mA    27.38mA
3V        25.18mA    20.44mA    30.63mA
[POWER Clamp]
|   Voltage   I(typ)   I(min)   I(max)
-1.5V     4.102mA    4.257mA    5.592mA
-1.35V    6.884mA    7.015mA    8.776mA
-1.1V     12.02mA    14.02mA    13.35mA
-960mV    14.11mA    16.51mA    14.54mA
-810mV    14.34mA    16.65mA    13.99mA
-630mV    13.04mA    14.9mA     12.77mA
-490mV    10.88mA    12.11mA    11.01mA
145mV     -2.971mA   -3.211mA   -3.092mA
720mV     -12.16mA   -12.13mA   -13.5mA
1.065V    -15.23mA   -14.54mA   -17.69mA
1.44V     -17.01mA   -15.95mA   -20.4mA
3V        -21.12mA   -19.63mA   -25.7mA
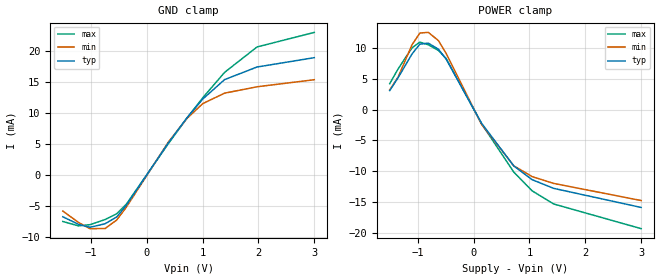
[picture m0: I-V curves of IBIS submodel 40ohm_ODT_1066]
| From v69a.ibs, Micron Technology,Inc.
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|   SUBMODEL 40ohm_ODT_1066
[Submodel]  40ohm_ODT_1066
Submodel_type   Dynamic_clamp
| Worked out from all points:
|   POWER clamp passes 1 mA (typ) near -0.06 V on its own axis
[GND Clamp]
|   Voltage   I(typ)   I(min)   I(max)
-1.5V     -6.799mA   -5.877mA   -7.558mA
-1.22V    -8.022mA   -7.716mA   -8.272mA
-1.015V   -8.504mA   -8.718mA   -8.074mA
-745mV    -7.927mA   -8.701mA   -7.251mA
-535mV    -6.82mA    -7.313mA   -6.307mA
-365mV    -4.963mA   -5.268mA   -4.782mA
385mV     5.095mA    5.226mA    4.973mA
720mV     9.163mA    9.076mA    9.111mA
1.005V    12.22mA    11.48mA    12.43mA
1.395V    15.35mA    13.16mA    16.52mA
1.975V    17.38mA    14.19mA    20.62mA
3V        18.89mA    15.33mA    22.97mA
[POWER Clamp]
|   Voltage   I(typ)   I(min)   I(max)
-1.5V     3.076mA    3.193mA    4.194mA
-1.35V    5.163mA    5.261mA    6.582mA
-1.1V     9.014mA    10.51mA    10.01mA
-960mV    10.59mA    12.39mA    10.91mA
-810mV    10.75mA    12.49mA    10.49mA
-630mV    9.781mA    11.18mA    9.577mA
-490mV    8.16mA     9.083mA    8.259mA
145mV     -2.228mA   -2.408mA   -2.319mA
720mV     -9.123mA   -9.098mA   -10.12mA
1.05V     -11.35mA   -10.85mA   -13.16mA
1.435V    -12.75mA   -11.95mA   -15.28mA
3V        -15.84mA   -14.72mA   -19.27mA
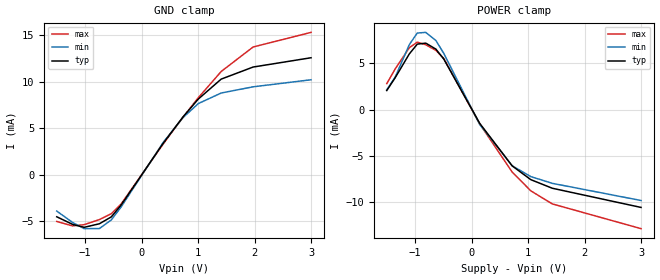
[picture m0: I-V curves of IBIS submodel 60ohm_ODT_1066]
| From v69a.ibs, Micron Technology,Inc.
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|   SUBMODEL 60ohm_ODT_1066
[Submodel]  60ohm_ODT_1066
Submodel_type   Dynamic_clamp
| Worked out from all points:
|   POWER clamp passes 1 mA (typ) near -0.09 V on its own axis
[GND Clamp]
|   Voltage   I(typ)   I(min)   I(max)
-1.5V     -4.533mA   -3.918mA   -5.039mA
-1.22V    -5.348mA   -5.144mA   -5.515mA
-1.015V   -5.669mA   -5.812mA   -5.383mA
-745mV    -5.285mA   -5.801mA   -4.834mA
-535mV    -4.547mA   -4.875mA   -4.205mA
-365mV    -3.309mA   -3.512mA   -3.188mA
385mV     3.396mA    3.484mA    3.315mA
735mV     6.223mA    6.15mA     6.194mA
1.005V    8.144mA    7.654mA    8.288mA
1.41V     10.29mA    8.794mA    11.11mA
1.975V    11.59mA    9.46mA     13.75mA
3V        12.59mA    10.22mA    15.32mA
[POWER Clamp]
|   Voltage   I(typ)   I(min)   I(max)
-1.5V     2.051mA    2.128mA    2.796mA
-1.35V    3.442mA    3.508mA    4.388mA
-1.1V     6.009mA    7.008mA    6.676mA
-960mV    7.057mA    8.257mA    7.271mA
-810mV    7.168mA    8.325mA    6.994mA
-630mV    6.521mA    7.451mA    6.385mA
-490mV    5.44mA     6.055mA    5.506mA
145mV     -1.485mA   -1.606mA   -1.546mA
720mV     -6.082mA   -6.065mA   -6.749mA
1.05V     -7.564mA   -7.236mA   -8.772mA
1.43V     -8.49mA    -7.961mA   -10.18mA
3V        -10.56mA   -9.813mA   -12.85mA
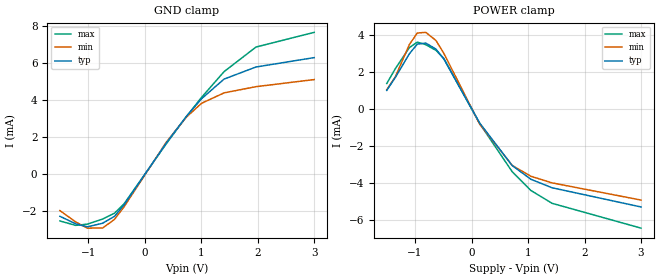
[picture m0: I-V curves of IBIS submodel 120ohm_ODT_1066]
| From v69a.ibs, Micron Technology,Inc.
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|   SUBMODEL 120ohm_ODT_1066
[Submodel]  120ohm_ODT_1066
Submodel_type   Dynamic_clamp
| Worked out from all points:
|   POWER clamp passes 1 mA (typ) near -0.18 V on its own axis
[GND Clamp]
|   Voltage   I(typ)   I(min)   I(max)
-1.5V     -2.266mA   -1.959mA   -2.519mA
-1.22V    -2.674mA   -2.572mA   -2.757mA
-1.015V   -2.835mA   -2.906mA   -2.691mA
-745mV    -2.642mA   -2.9mA     -2.417mA
-535mV    -2.273mA   -2.438mA   -2.102mA
-365mV    -1.654mA   -1.756mA   -1.594mA
385mV     1.698mA    1.742mA    1.658mA
735mV     3.112mA    3.075mA    3.097mA
1.005V    4.072mA    3.827mA    4.144mA
1.405V    5.137mA    4.393mA    5.538mA
1.97V     5.789mA    4.728mA    6.866mA
3V        6.296mA    5.111mA    7.658mA
[POWER Clamp]
|   Voltage   I(typ)   I(min)   I(max)
-1.5V     1.026mA    1.064mA    1.398mA
-1.35V    1.721mA    1.754mA    2.194mA
-1.1V     3.005mA    3.505mA    3.338mA
-960mV    3.528mA    4.129mA    3.635mA
-810mV    3.584mA    4.163mA    3.497mA
-630mV    3.26mA     3.725mA    3.192mA
-490mV    2.72mA     3.028mA    2.753mA
145mV     -742.7uA   -802.8uA   -772.9uA
720mV     -3.041mA   -3.033mA   -3.374mA
1.05V     -3.782mA   -3.618mA   -4.386mA
1.425V    -4.24mA    -3.976mA   -5.081mA
3V        -5.279mA   -4.906mA   -6.424mA
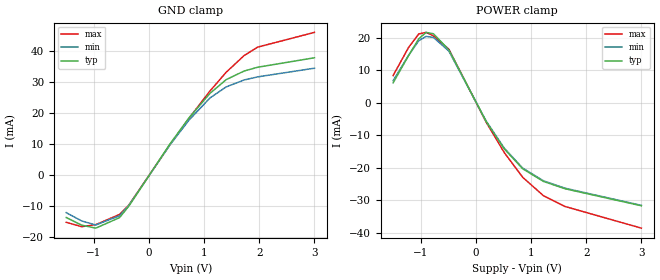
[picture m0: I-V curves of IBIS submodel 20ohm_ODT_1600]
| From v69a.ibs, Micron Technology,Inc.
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|   SUBMODEL 20ohm_ODT_1600
[Submodel]  20ohm_ODT_1600
Submodel_type   Dynamic_clamp
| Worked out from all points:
|   POWER clamp passes 1 mA (typ) near -0.03 V on its own axis
[GND Clamp]
|   Voltage   I(typ)   I(min)   I(max)
-1.5V     -13.6mA    -12.02mA   -15.12mA
-1.22V    -16.04mA   -14.69mA   -16.54mA
-965mV    -17mA      -15.99mA   -15.88mA
-535mV    -13.64mA   -13.02mA   -12.61mA
-365mV    -9.926mA   -9.678mA   -9.564mA
375mV     9.931mA    9.644mA    9.691mA
725mV     18.44mA    17.72mA    18.34mA
1.105V    26.32mA    24.85mA    27.08mA
1.4V      30.76mA    28.42mA    33.13mA
1.725V    33.52mA    30.64mA    38.5mA
1.97V     34.74mA    31.64mA    41.2mA
3V        37.78mA    34.43mA    45.95mA
[POWER Clamp]
|   Voltage   I(typ)   I(min)   I(max)
-1.5V     6.153mA    6.805mA    8.388mA
-1.22V    14.52mA    14.6mA     17.03mA
-1.035V   19.71mA    19.12mA    21.21mA
-900mV    21.67mA    20.44mA    21.68mA
-770mV    21.26mA    20.13mA    20.62mA
-490mV    16.32mA    15.95mA    16.52mA
185mV     -5.673mA   -5.566mA   -5.894mA
515mV     -14.17mA   -13.95mA   -15.31mA
850mV     -20.3mA    -20.09mA   -22.92mA
1.225V    -24.17mA   -23.98mA   -28.57mA
1.615V    -26.42mA   -26.26mA   -31.88mA
3V        -31.67mA   -31.54mA   -38.55mA
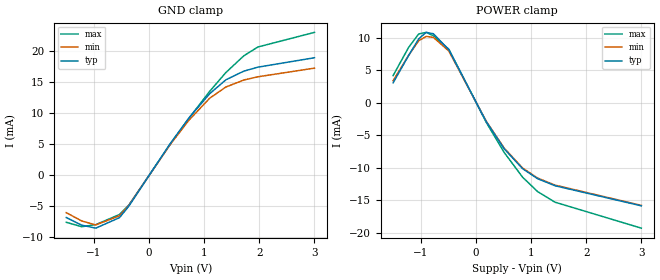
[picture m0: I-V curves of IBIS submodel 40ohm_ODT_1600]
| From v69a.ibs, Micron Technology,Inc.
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|   SUBMODEL 40ohm_ODT_1600
[Submodel]  40ohm_ODT_1600
Submodel_type   Dynamic_clamp
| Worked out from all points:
|   POWER clamp passes 1 mA (typ) near -0.06 V on its own axis
[GND Clamp]
|   Voltage   I(typ)   I(min)   I(max)
-1.5V     -6.799mA   -6.012mA   -7.558mA
-1.22V    -8.022mA   -7.346mA   -8.272mA
-965mV    -8.501mA   -7.994mA   -7.94mA
-535mV    -6.82mA    -6.511mA   -6.307mA
-365mV    -4.963mA   -4.839mA   -4.782mA
375mV     4.966mA    4.822mA    4.846mA
725mV     9.22mA     8.86mA     9.171mA
1.1V      13.11mA    12.38mA    13.49mA
1.395V    15.35mA    14.19mA    16.52mA
1.72V     16.74mA    15.31mA    19.21mA
1.975V    17.38mA    15.83mA    20.62mA
3V        18.89mA    17.22mA    22.97mA
[POWER Clamp]
|   Voltage   I(typ)   I(min)   I(max)
-1.5V     3.076mA    3.403mA    4.194mA
-1.22V    7.262mA    7.299mA    8.514mA
-1.035V   9.857mA    9.558mA    10.6mA
-900mV    10.84mA    10.22mA    10.84mA
-770mV    10.63mA    10.07mA    10.31mA
-490mV    8.16mA     7.973mA    8.259mA
185mV     -2.836mA   -2.783mA   -2.947mA
515mV     -7.085mA   -6.974mA   -7.654mA
850mV     -10.15mA   -10.04mA   -11.46mA
1.12V     -11.67mA   -11.57mA   -13.65mA
1.435V    -12.75mA   -12.65mA   -15.28mA
3V        -15.84mA   -15.77mA   -19.27mA
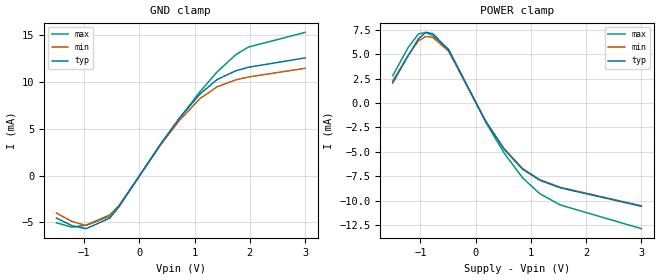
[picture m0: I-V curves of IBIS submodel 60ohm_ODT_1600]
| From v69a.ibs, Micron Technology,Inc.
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|   SUBMODEL 60ohm_ODT_1600
[Submodel]  60ohm_ODT_1600
Submodel_type   Dynamic_clamp
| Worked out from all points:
|   POWER clamp passes 1 mA (typ) near -0.09 V on its own axis
[GND Clamp]
|   Voltage   I(typ)   I(min)   I(max)
-1.5V     -4.533mA   -4.008mA   -5.039mA
-1.22V    -5.348mA   -4.897mA   -5.515mA
-965mV    -5.668mA   -5.329mA   -5.293mA
-535mV    -4.547mA   -4.34mA    -4.205mA
-365mV    -3.309mA   -3.226mA   -3.188mA
375mV     3.31mA     3.215mA    3.23mA
725mV     6.147mA    5.907mA    6.114mA
1.1V      8.742mA    8.256mA    8.991mA
1.41V     10.29mA    9.504mA    11.11mA
1.745V    11.21mA    10.24mA    12.93mA
1.975V    11.59mA    10.55mA    13.75mA
3V        12.59mA    11.48mA    15.32mA
[POWER Clamp]
|   Voltage   I(typ)   I(min)   I(max)
-1.5V     2.051mA    2.268mA    2.796mA
-1.22V    4.841mA    4.866mA    5.676mA
-1.035V   6.571mA    6.372mA    7.07mA
-900mV    7.224mA    6.812mA    7.227mA
-770mV    7.088mA    6.71mA     6.874mA
-490mV    5.44mA     5.315mA    5.506mA
185mV     -1.891mA   -1.855mA   -1.965mA
515mV     -4.724mA   -4.649mA   -5.103mA
850mV     -6.768mA   -6.695mA   -7.641mA
1.16V     -7.891mA   -7.828mA   -9.269mA
1.535V    -8.676mA   -8.62mA    -10.43mA
3V        -10.56mA   -10.51mA   -12.85mA
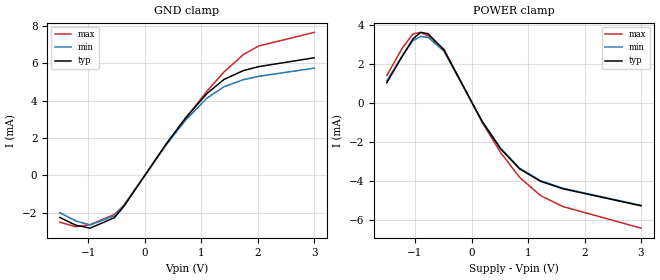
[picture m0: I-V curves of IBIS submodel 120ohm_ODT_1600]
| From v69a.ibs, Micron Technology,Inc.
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|   SUBMODEL 120ohm_ODT_1600
[Submodel]  120ohm_ODT_1600
Submodel_type   Dynamic_clamp
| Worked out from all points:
|   POWER clamp passes 1 mA (typ) near -0.18 V on its own axis
[GND Clamp]
|   Voltage   I(typ)   I(min)   I(max)
-1.5V     -2.266mA   -2.004mA   -2.519mA
-1.22V    -2.674mA   -2.449mA   -2.757mA
-965mV    -2.834mA   -2.665mA   -2.647mA
-535mV    -2.273mA   -2.17mA    -2.102mA
-365mV    -1.654mA   -1.613mA   -1.594mA
375mV     1.655mA    1.607mA    1.615mA
725mV     3.073mA    2.953mA    3.057mA
1.105V    4.386mA    4.141mA    4.514mA
1.405V    5.137mA    4.745mA    5.538mA
1.745V    5.607mA    5.121mA    6.463mA
2.015V    5.82mA     5.301mA    6.926mA
3V        6.296mA    5.739mA    7.658mA
[POWER Clamp]
|   Voltage   I(typ)   I(min)   I(max)
-1.5V     1.026mA    1.134mA    1.398mA
-1.22V    2.421mA    2.433mA    2.838mA
-1.035V   3.286mA    3.186mA    3.535mA
-900mV    3.612mA    3.406mA    3.613mA
-770mV    3.544mA    3.355mA    3.437mA
-490mV    2.72mA     2.658mA    2.753mA
185mV     -945.4uA   -927.7uA   -982.4uA
515mV     -2.362mA   -2.325mA   -2.551mA
850mV     -3.384mA   -3.348mA   -3.82mA
1.225V    -4.028mA   -3.997mA   -4.762mA
1.62V     -4.408mA   -4.38mA    -5.318mA
3V        -5.279mA   -5.256mA   -6.424mA
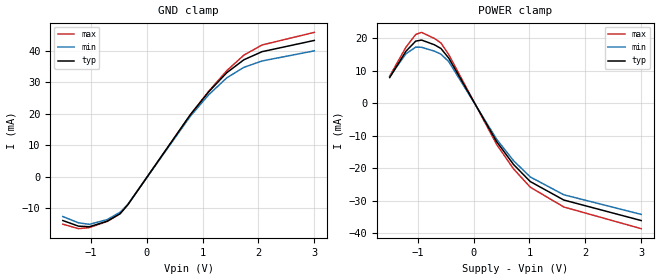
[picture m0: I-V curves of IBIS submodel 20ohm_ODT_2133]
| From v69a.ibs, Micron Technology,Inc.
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|   SUBMODEL 20ohm_ODT_2133
[Submodel]  20ohm_ODT_2133
Submodel_type   Dynamic_clamp
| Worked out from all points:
|   GND clamp passes 1 mA (typ) near -0.04 V on its own axis
|   POWER clamp passes 1 mA (typ) near -0.03 V on its own axis
[GND Clamp]
|   Voltage   I(typ)   I(min)   I(max)
-1.5V     -13.96mA   -12.69mA   -15.12mA
-1.22V    -15.74mA   -14.68mA   -16.54mA
-1.025V   -15.93mA   -15.17mA   -16.2mA
-705mV    -14.15mA   -13.64mA   -14.23mA
-475mV    -11.78mA   -11.3mA    -11.77mA
-335mV    -8.889mA   -8.744mA   -8.802mA
780mV     19.71mA    19.22mA    19.66mA
1.11V     27.03mA    26.1mA     27.19mA
1.435V    33.14mA    31.5mA     33.79mA
1.74V     37.24mA    34.83mA    38.71mA
2.065V    39.81mA    36.85mA    41.95mA
3V        43.39mA    40.08mA    45.95mA
[POWER Clamp]
|   Voltage   I(typ)   I(min)   I(max)
-1.5V     7.95mA     8.248mA    8.388mA
-1.21V    16.04mA    15.27mA    17.28mA
-1.035V   19.15mA    17.31mA    21.21mA
-930mV    19.48mA    17.26mA    21.84mA
-700mV    18.03mA    16.07mA    19.98mA
-585mV    16.91mA    15.16mA    18.62mA
-445mV    13.97mA    12.88mA    15.05mA
415mV     -11.81mA   -11.07mA   -12.68mA
715mV     -18.79mA   -17.63mA   -20.14mA
1.015V    -24.06mA   -22.64mA   -25.79mA
1.615V    -29.74mA   -28.12mA   -31.88mA
3V        -36.05mA   -34.16mA   -38.55mA
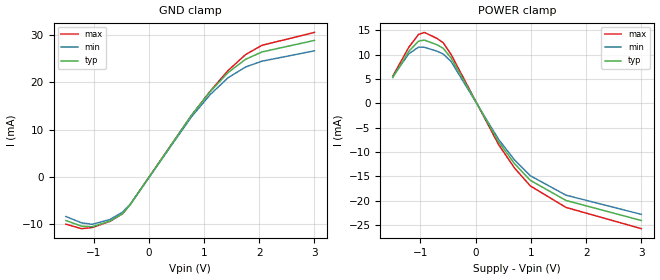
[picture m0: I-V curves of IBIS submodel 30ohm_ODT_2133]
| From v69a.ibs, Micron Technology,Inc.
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|   SUBMODEL 30ohm_ODT_2133
[Submodel]  30ohm_ODT_2133
Submodel_type   Dynamic_clamp
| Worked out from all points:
|   GND clamp passes 1 mA (typ) near -0.06 V on its own axis
|   POWER clamp passes 1 mA (typ) near -0.05 V on its own axis
[GND Clamp]
|   Voltage   I(typ)   I(min)   I(max)
-1.5V     -9.307mA   -8.459mA   -10.08mA
-1.22V    -10.49mA   -9.784mA   -11.03mA
-1.025V   -10.62mA   -10.11mA   -10.8mA
-705mV    -9.43mA    -9.094mA   -9.484mA
-475mV    -7.855mA   -7.534mA   -7.848mA
-335mV    -5.926mA   -5.829mA   -5.868mA
770mV     12.99mA    12.66mA    12.95mA
1.11V     18.02mA    17.4mA     18.13mA
1.435V    22.1mA     21mA       22.53mA
1.755V    24.93mA    23.3mA     25.94mA
2.05V     26.48mA    24.52mA    27.89mA
3V        28.93mA    26.72mA    30.63mA
[POWER Clamp]
|   Voltage   I(typ)   I(min)   I(max)
-1.5V     5.3mA      5.499mA    5.592mA
-1.21V    10.69mA    10.18mA    11.52mA
-1.035V   12.77mA    11.54mA    14.14mA
-930mV    12.99mA    11.51mA    14.56mA
-700mV    12.02mA    10.71mA    13.32mA
-585mV    11.28mA    10.11mA    12.41mA
-445mV    9.313mA    8.584mA    10.03mA
415mV     -7.872mA   -7.38mA    -8.451mA
705mV     -12.39mA   -11.62mA   -13.28mA
990mV     -15.79mA   -14.85mA   -16.93mA
1.635V    -19.91mA   -18.83mA   -21.34mA
3V        -24.03mA   -22.77mA   -25.7mA
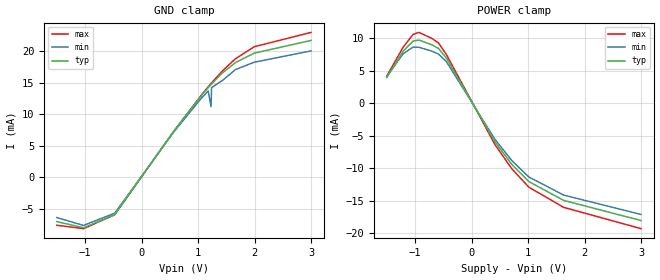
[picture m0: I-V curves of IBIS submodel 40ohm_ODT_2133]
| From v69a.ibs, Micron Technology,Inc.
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|   SUBMODEL 40ohm_ODT_2133
[Submodel]  40ohm_ODT_2133
Submodel_type   Dynamic_clamp
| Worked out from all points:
|   GND clamp passes 1 mA (typ) near -0.07 V on its own axis
|   POWER clamp passes 1 mA (typ) near -0.06 V on its own axis
[GND Clamp]
-1.5V     -6.98mA    -6.344mA   -7.558mA
-1.025V   -7.965mA   -7.585mA   -8.1mA
-475mV    -5.891mA   -5.65mA    -5.886mA
570mV     7.325mA    7.187mA    7.285mA
1.055V    12.94mA    12.51mA    12.99mA
1.18V     14.23mA    13.7mA     14.35mA
1.23V     14.72mA    11.23mA    14.88mA
1.24V     14.82mA    14.23mA    14.98mA
1.435V    16.57mA    15.38mA    16.9mA
1.66V     18.18mA    17.07mA    18.78mA
1.995V    19.69mA    18.25mA    20.7mA
3V        21.7mA     20.04mA    22.97mA
[POWER Clamp]
|   Voltage   I(typ)   I(min)   I(max)
-1.5V     3.975mA    4.124mA    4.194mA
-1.21V    8.018mA    7.633mA    8.64mA
-1.035V   9.576mA    8.655mA    10.6mA
-930mV    9.742mA    8.63mA     10.92mA
-700mV    9.015mA    8.036mA    9.992mA
-585mV    8.457mA    7.58mA     9.309mA
-445mV    6.985mA    6.438mA    7.524mA
415mV     -5.904mA   -5.535mA   -6.338mA
715mV     -9.393mA   -8.815mA   -10.07mA
1.015V    -12.03mA   -11.32mA   -12.89mA
1.63V     -14.92mA   -14.1mA    -15.99mA
3V        -18.02mA   -17.08mA   -19.27mA
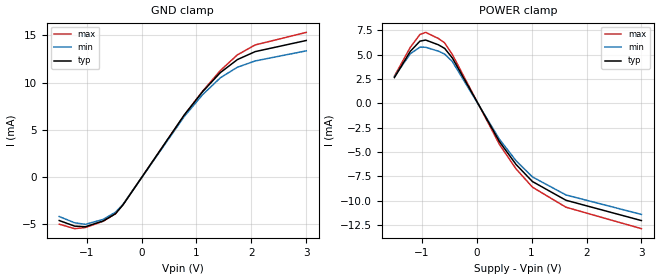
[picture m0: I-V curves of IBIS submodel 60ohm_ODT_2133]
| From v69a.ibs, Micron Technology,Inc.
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|   SUBMODEL 60ohm_ODT_2133
[Submodel]  60ohm_ODT_2133
Submodel_type   Dynamic_clamp
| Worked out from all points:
|   GND clamp passes 1 mA (typ) near -0.11 V on its own axis
|   POWER clamp passes 1 mA (typ) near -0.10 V on its own axis
[GND Clamp]
|   Voltage   I(typ)   I(min)   I(max)
-1.5V     -4.653mA   -4.229mA   -5.039mA
-1.22V    -5.245mA   -4.892mA   -5.515mA
-1.025V   -5.31mA    -5.057mA   -5.4mA
-700mV    -4.703mA   -4.533mA   -4.729mA
-475mV    -3.927mA   -3.767mA   -3.924mA
-335mV    -2.963mA   -2.915mA   -2.934mA
780mV     6.571mA    6.407mA    6.552mA
1.11V     9.011mA    8.699mA    9.064mA
1.435V    11.05mA    10.5mA     11.27mA
1.745V    12.43mA    11.62mA    12.93mA
2.07V     13.28mA    12.29mA    13.99mA
3V        14.46mA    13.36mA    15.32mA
[POWER Clamp]
|   Voltage   I(typ)   I(min)   I(max)
-1.5V     2.65mA     2.749mA    2.796mA
-1.21V    5.345mA    5.089mA    5.76mA
-1.035V   6.384mA    5.77mA     7.07mA
-930mV    6.495mA    5.753mA    7.28mA
-700mV    6.01mA     5.357mA    6.661mA
-585mV    5.638mA    5.053mA    6.206mA
-445mV    4.657mA    4.292mA    5.016mA
415mV     -3.936mA   -3.69mA    -4.225mA
715mV     -6.262mA   -5.877mA   -6.712mA
1.015V    -8.019mA   -7.545mA   -8.596mA
1.625V    -9.936mA   -9.393mA   -10.65mA
3V        -12.02mA   -11.39mA   -12.85mA
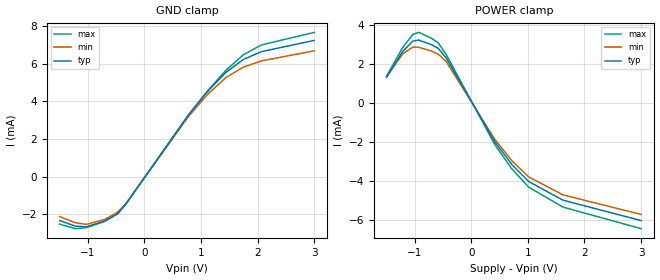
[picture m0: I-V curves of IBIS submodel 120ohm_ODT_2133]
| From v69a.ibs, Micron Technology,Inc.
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|   SUBMODEL 120ohm_ODT_2133
[Submodel]  120ohm_ODT_2133
Submodel_type   Dynamic_clamp
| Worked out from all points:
|   GND clamp passes 1 mA (typ) near -0.22 V on its own axis
|   POWER clamp passes 1 mA (typ) near -0.19 V on its own axis
[GND Clamp]
|   Voltage   I(typ)   I(min)   I(max)
-1.5V     -2.327mA   -2.115mA   -2.519mA
-1.22V    -2.623mA   -2.446mA   -2.757mA
-1.025V   -2.655mA   -2.528mA   -2.7mA
-700mV    -2.351mA   -2.266mA   -2.365mA
-475mV    -1.964mA   -1.883mA   -1.962mA
-335mV    -1.481mA   -1.457mA   -1.467mA
780mV     3.285mA    3.204mA    3.276mA
1.11V     4.505mA    4.35mA     4.532mA
1.435V    5.524mA    5.25mA     5.632mA
1.745V    6.215mA    5.812mA    6.463mA
2.065V    6.635mA    6.142mA    6.991mA
3V        7.232mA    6.681mA    7.658mA
[POWER Clamp]
|   Voltage   I(typ)   I(min)   I(max)
-1.5V     1.325mA    1.375mA    1.398mA
-1.21V    2.673mA    2.545mA    2.88mA
-1.035V   3.192mA    2.885mA    3.535mA
-930mV    3.247mA    2.877mA    3.64mA
-700mV    3.005mA    2.679mA    3.331mA
-585mV    2.819mA    2.527mA    3.103mA
-445mV    2.328mA    2.146mA    2.508mA
415mV     -1.968mA   -1.845mA   -2.113mA
715mV     -3.131mA   -2.938mA   -3.356mA
1.015V    -4.009mA   -3.773mA   -4.298mA
1.62V     -4.963mA   -4.692mA   -5.318mA
3V        -6.008mA   -5.693mA   -6.424mA
